VERSION 5.7 ;
  NOWIREEXTENSIONATPIN ON ;
  DIVIDERCHAR "/" ;
  BUSBITCHARS "[]" ;
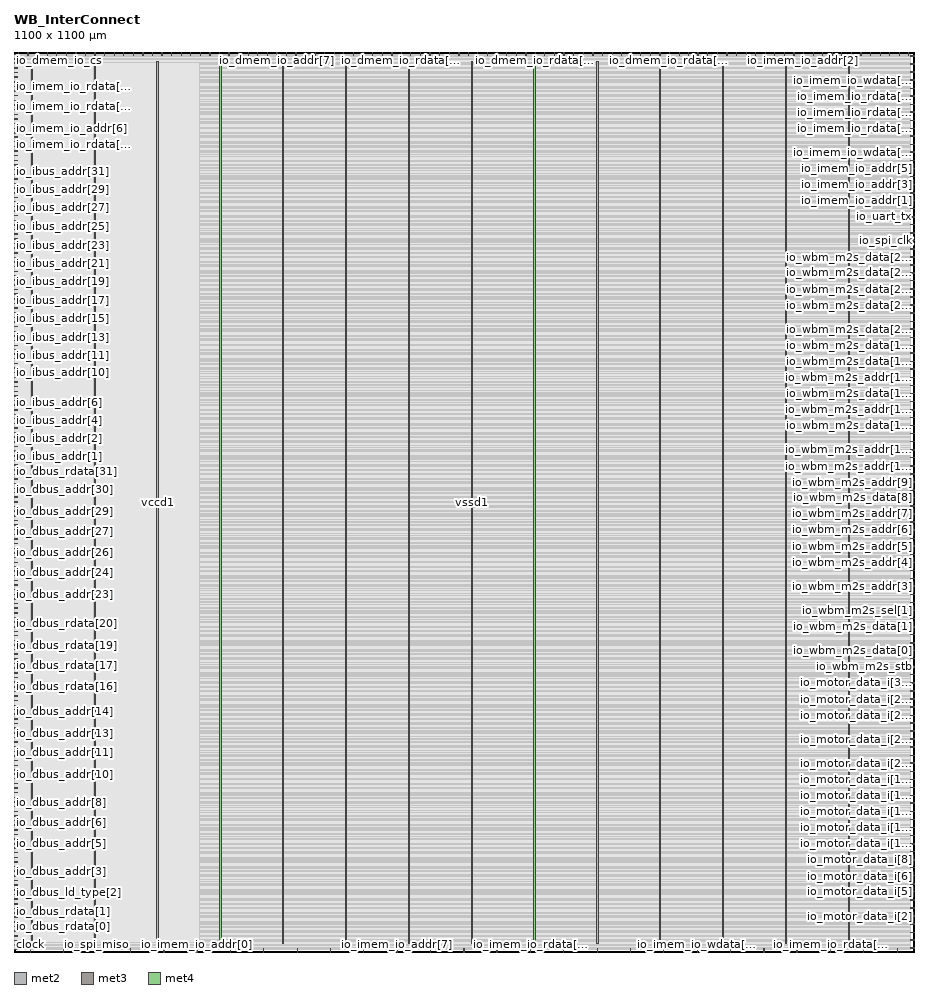
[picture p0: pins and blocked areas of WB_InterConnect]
MACRO WB_InterConnect
  CLASS BLOCK ;
  FOREIGN WB_InterConnect ;
  ORIGIN 0.000 0.000 ;
  SIZE 1100.000 BY 1100.000 ;
  PIN clock
    DIRECTION INPUT ;
    USE SIGNAL ;
    PORT
      LAYER met2 ;
        RECT 20.330 0.000 20.610 4.000 ;
    END
  END clock
  PIN io_dbus_addr[0]
    DIRECTION INPUT ;
    USE SIGNAL ;
    PORT
      LAYER met3 ;
        RECT 0.000 19.080 4.000 19.680 ;
    END
  END io_dbus_addr[0]
  PIN io_dbus_addr[10]
    DIRECTION INPUT ;
    USE SIGNAL ;
    PORT
      LAYER met3 ;
        RECT 0.000 216.960 4.000 217.560 ;
    END
  END io_dbus_addr[10]
  PIN io_dbus_addr[11]
    DIRECTION INPUT ;
    USE SIGNAL ;
    PORT
      LAYER met3 ;
        RECT 0.000 233.960 4.000 234.560 ;
    END
  END io_dbus_addr[11]
  PIN io_dbus_addr[12]
    DIRECTION INPUT ;
    USE SIGNAL ;
    PORT
      LAYER met3 ;
        RECT 0.000 250.960 4.000 251.560 ;
    END
  END io_dbus_addr[12]
  PIN io_dbus_addr[13]
    DIRECTION INPUT ;
    USE SIGNAL ;
    PORT
      LAYER met3 ;
        RECT 0.000 267.280 4.000 267.880 ;
    END
  END io_dbus_addr[13]
  PIN io_dbus_addr[14]
    DIRECTION INPUT ;
    USE SIGNAL ;
    PORT
      LAYER met3 ;
        RECT 0.000 284.280 4.000 284.880 ;
    END
  END io_dbus_addr[14]
  PIN io_dbus_addr[15]
    DIRECTION INPUT ;
    USE SIGNAL ;
    PORT
      LAYER met3 ;
        RECT 0.000 301.280 4.000 301.880 ;
    END
  END io_dbus_addr[15]
  PIN io_dbus_addr[16]
    DIRECTION INPUT ;
    USE SIGNAL ;
    PORT
      LAYER met3 ;
        RECT 0.000 318.280 4.000 318.880 ;
    END
  END io_dbus_addr[16]
  PIN io_dbus_addr[17]
    DIRECTION INPUT ;
    USE SIGNAL ;
    PORT
      LAYER met3 ;
        RECT 0.000 335.280 4.000 335.880 ;
    END
  END io_dbus_addr[17]
  PIN io_dbus_addr[18]
    DIRECTION INPUT ;
    USE SIGNAL ;
    PORT
      LAYER met3 ;
        RECT 0.000 352.280 4.000 352.880 ;
    END
  END io_dbus_addr[18]
  PIN io_dbus_addr[19]
    DIRECTION INPUT ;
    USE SIGNAL ;
    PORT
      LAYER met3 ;
        RECT 0.000 369.280 4.000 369.880 ;
    END
  END io_dbus_addr[19]
  PIN io_dbus_addr[1]
    DIRECTION INPUT ;
    USE SIGNAL ;
    PORT
      LAYER met3 ;
        RECT 0.000 47.640 4.000 48.240 ;
    END
  END io_dbus_addr[1]
  PIN io_dbus_addr[20]
    DIRECTION INPUT ;
    USE SIGNAL ;
    PORT
      LAYER met3 ;
        RECT 0.000 386.280 4.000 386.880 ;
    END
  END io_dbus_addr[20]
  PIN io_dbus_addr[21]
    DIRECTION INPUT ;
    USE SIGNAL ;
    PORT
      LAYER met3 ;
        RECT 0.000 403.280 4.000 403.880 ;
    END
  END io_dbus_addr[21]
  PIN io_dbus_addr[22]
    DIRECTION INPUT ;
    USE SIGNAL ;
    PORT
      LAYER met3 ;
        RECT 0.000 420.280 4.000 420.880 ;
    END
  END io_dbus_addr[22]
  PIN io_dbus_addr[23]
    DIRECTION INPUT ;
    USE SIGNAL ;
    PORT
      LAYER met3 ;
        RECT 0.000 436.600 4.000 437.200 ;
    END
  END io_dbus_addr[23]
  PIN io_dbus_addr[24]
    DIRECTION INPUT ;
    USE SIGNAL ;
    PORT
      LAYER met3 ;
        RECT 0.000 453.600 4.000 454.200 ;
    END
  END io_dbus_addr[24]
  PIN io_dbus_addr[25]
    DIRECTION INPUT ;
    USE SIGNAL ;
    PORT
      LAYER met3 ;
        RECT 0.000 470.600 4.000 471.200 ;
    END
  END io_dbus_addr[25]
  PIN io_dbus_addr[26]
    DIRECTION INPUT ;
    USE SIGNAL ;
    PORT
      LAYER met3 ;
        RECT 0.000 487.600 4.000 488.200 ;
    END
  END io_dbus_addr[26]
  PIN io_dbus_addr[27]
    DIRECTION INPUT ;
    USE SIGNAL ;
    PORT
      LAYER met3 ;
        RECT 0.000 504.600 4.000 505.200 ;
    END
  END io_dbus_addr[27]
  PIN io_dbus_addr[28]
    DIRECTION INPUT ;
    USE SIGNAL ;
    PORT
      LAYER met3 ;
        RECT 0.000 521.600 4.000 522.200 ;
    END
  END io_dbus_addr[28]
  PIN io_dbus_addr[29]
    DIRECTION INPUT ;
    USE SIGNAL ;
    PORT
      LAYER met3 ;
        RECT 0.000 538.600 4.000 539.200 ;
    END
  END io_dbus_addr[29]
  PIN io_dbus_addr[2]
    DIRECTION INPUT ;
    USE SIGNAL ;
    PORT
      LAYER met3 ;
        RECT 0.000 75.520 4.000 76.120 ;
    END
  END io_dbus_addr[2]
  PIN io_dbus_addr[30]
    DIRECTION INPUT ;
    USE SIGNAL ;
    PORT
      LAYER met3 ;
        RECT 0.000 555.600 4.000 556.200 ;
    END
  END io_dbus_addr[30]
  PIN io_dbus_addr[31]
    DIRECTION INPUT ;
    USE SIGNAL ;
    PORT
      LAYER met3 ;
        RECT 0.000 572.600 4.000 573.200 ;
    END
  END io_dbus_addr[31]
  PIN io_dbus_addr[3]
    DIRECTION INPUT ;
    USE SIGNAL ;
    PORT
      LAYER met3 ;
        RECT 0.000 98.640 4.000 99.240 ;
    END
  END io_dbus_addr[3]
  PIN io_dbus_addr[4]
    DIRECTION INPUT ;
    USE SIGNAL ;
    PORT
      LAYER met3 ;
        RECT 0.000 114.960 4.000 115.560 ;
    END
  END io_dbus_addr[4]
  PIN io_dbus_addr[5]
    DIRECTION INPUT ;
    USE SIGNAL ;
    PORT
      LAYER met3 ;
        RECT 0.000 131.960 4.000 132.560 ;
    END
  END io_dbus_addr[5]
  PIN io_dbus_addr[6]
    DIRECTION INPUT ;
    USE SIGNAL ;
    PORT
      LAYER met3 ;
        RECT 0.000 148.960 4.000 149.560 ;
    END
  END io_dbus_addr[6]
  PIN io_dbus_addr[7]
    DIRECTION INPUT ;
    USE SIGNAL ;
    PORT
      LAYER met3 ;
        RECT 0.000 165.960 4.000 166.560 ;
    END
  END io_dbus_addr[7]
  PIN io_dbus_addr[8]
    DIRECTION INPUT ;
    USE SIGNAL ;
    PORT
      LAYER met3 ;
        RECT 0.000 182.960 4.000 183.560 ;
    END
  END io_dbus_addr[8]
  PIN io_dbus_addr[9]
    DIRECTION INPUT ;
    USE SIGNAL ;
    PORT
      LAYER met3 ;
        RECT 0.000 199.960 4.000 200.560 ;
    END
  END io_dbus_addr[9]
  PIN io_dbus_ld_type[0]
    DIRECTION INPUT ;
    USE SIGNAL ;
    PORT
      LAYER met3 ;
        RECT 0.000 25.200 4.000 25.800 ;
    END
  END io_dbus_ld_type[0]
  PIN io_dbus_ld_type[1]
    DIRECTION INPUT ;
    USE SIGNAL ;
    PORT
      LAYER met3 ;
        RECT 0.000 53.080 4.000 53.680 ;
    END
  END io_dbus_ld_type[1]
  PIN io_dbus_ld_type[2]
    DIRECTION INPUT ;
    USE SIGNAL ;
    PORT
      LAYER met3 ;
        RECT 0.000 81.640 4.000 82.240 ;
    END
  END io_dbus_ld_type[2]
  PIN io_dbus_rd_en
    DIRECTION INPUT ;
    USE SIGNAL ;
    PORT
      LAYER met3 ;
        RECT 0.000 2.760 4.000 3.360 ;
    END
  END io_dbus_rd_en
  PIN io_dbus_rdata[0]
    DIRECTION OUTPUT TRISTATE ;
    USE SIGNAL ;
    PORT
      LAYER met3 ;
        RECT 0.000 30.640 4.000 31.240 ;
    END
  END io_dbus_rdata[0]
  PIN io_dbus_rdata[10]
    DIRECTION OUTPUT TRISTATE ;
    USE SIGNAL ;
    PORT
      LAYER met3 ;
        RECT 0.000 222.400 4.000 223.000 ;
    END
  END io_dbus_rdata[10]
  PIN io_dbus_rdata[11]
    DIRECTION OUTPUT TRISTATE ;
    USE SIGNAL ;
    PORT
      LAYER met3 ;
        RECT 0.000 239.400 4.000 240.000 ;
    END
  END io_dbus_rdata[11]
  PIN io_dbus_rdata[12]
    DIRECTION OUTPUT TRISTATE ;
    USE SIGNAL ;
    PORT
      LAYER met3 ;
        RECT 0.000 256.400 4.000 257.000 ;
    END
  END io_dbus_rdata[12]
  PIN io_dbus_rdata[13]
    DIRECTION OUTPUT TRISTATE ;
    USE SIGNAL ;
    PORT
      LAYER met3 ;
        RECT 0.000 273.400 4.000 274.000 ;
    END
  END io_dbus_rdata[13]
  PIN io_dbus_rdata[14]
    DIRECTION OUTPUT TRISTATE ;
    USE SIGNAL ;
    PORT
      LAYER met3 ;
        RECT 0.000 290.400 4.000 291.000 ;
    END
  END io_dbus_rdata[14]
  PIN io_dbus_rdata[15]
    DIRECTION OUTPUT TRISTATE ;
    USE SIGNAL ;
    PORT
      LAYER met3 ;
        RECT 0.000 307.400 4.000 308.000 ;
    END
  END io_dbus_rdata[15]
  PIN io_dbus_rdata[16]
    DIRECTION OUTPUT TRISTATE ;
    USE SIGNAL ;
    PORT
      LAYER met3 ;
        RECT 0.000 323.720 4.000 324.320 ;
    END
  END io_dbus_rdata[16]
  PIN io_dbus_rdata[17]
    DIRECTION OUTPUT TRISTATE ;
    USE SIGNAL ;
    PORT
      LAYER met3 ;
        RECT 0.000 340.720 4.000 341.320 ;
    END
  END io_dbus_rdata[17]
  PIN io_dbus_rdata[18]
    DIRECTION OUTPUT TRISTATE ;
    USE SIGNAL ;
    PORT
      LAYER met3 ;
        RECT 0.000 357.720 4.000 358.320 ;
    END
  END io_dbus_rdata[18]
  PIN io_dbus_rdata[19]
    DIRECTION OUTPUT TRISTATE ;
    USE SIGNAL ;
    PORT
      LAYER met3 ;
        RECT 0.000 374.720 4.000 375.320 ;
    END
  END io_dbus_rdata[19]
  PIN io_dbus_rdata[1]
    DIRECTION OUTPUT TRISTATE ;
    USE SIGNAL ;
    PORT
      LAYER met3 ;
        RECT 0.000 58.520 4.000 59.120 ;
    END
  END io_dbus_rdata[1]
  PIN io_dbus_rdata[20]
    DIRECTION OUTPUT TRISTATE ;
    USE SIGNAL ;
    PORT
      LAYER met3 ;
        RECT 0.000 391.720 4.000 392.320 ;
    END
  END io_dbus_rdata[20]
  PIN io_dbus_rdata[21]
    DIRECTION OUTPUT TRISTATE ;
    USE SIGNAL ;
    PORT
      LAYER met3 ;
        RECT 0.000 408.720 4.000 409.320 ;
    END
  END io_dbus_rdata[21]
  PIN io_dbus_rdata[22]
    DIRECTION OUTPUT TRISTATE ;
    USE SIGNAL ;
    PORT
      LAYER met3 ;
        RECT 0.000 425.720 4.000 426.320 ;
    END
  END io_dbus_rdata[22]
  PIN io_dbus_rdata[23]
    DIRECTION OUTPUT TRISTATE ;
    USE SIGNAL ;
    PORT
      LAYER met3 ;
        RECT 0.000 442.720 4.000 443.320 ;
    END
  END io_dbus_rdata[23]
  PIN io_dbus_rdata[24]
    DIRECTION OUTPUT TRISTATE ;
    USE SIGNAL ;
    PORT
      LAYER met3 ;
        RECT 0.000 459.720 4.000 460.320 ;
    END
  END io_dbus_rdata[24]
  PIN io_dbus_rdata[25]
    DIRECTION OUTPUT TRISTATE ;
    USE SIGNAL ;
    PORT
      LAYER met3 ;
        RECT 0.000 476.040 4.000 476.640 ;
    END
  END io_dbus_rdata[25]
  PIN io_dbus_rdata[26]
    DIRECTION OUTPUT TRISTATE ;
    USE SIGNAL ;
    PORT
      LAYER met3 ;
        RECT 0.000 493.040 4.000 493.640 ;
    END
  END io_dbus_rdata[26]
  PIN io_dbus_rdata[27]
    DIRECTION OUTPUT TRISTATE ;
    USE SIGNAL ;
    PORT
      LAYER met3 ;
        RECT 0.000 510.040 4.000 510.640 ;
    END
  END io_dbus_rdata[27]
  PIN io_dbus_rdata[28]
    DIRECTION OUTPUT TRISTATE ;
    USE SIGNAL ;
    PORT
      LAYER met3 ;
        RECT 0.000 527.040 4.000 527.640 ;
    END
  END io_dbus_rdata[28]
  PIN io_dbus_rdata[29]
    DIRECTION OUTPUT TRISTATE ;
    USE SIGNAL ;
    PORT
      LAYER met3 ;
        RECT 0.000 544.040 4.000 544.640 ;
    END
  END io_dbus_rdata[29]
  PIN io_dbus_rdata[2]
    DIRECTION OUTPUT TRISTATE ;
    USE SIGNAL ;
    PORT
      LAYER met3 ;
        RECT 0.000 87.080 4.000 87.680 ;
    END
  END io_dbus_rdata[2]
  PIN io_dbus_rdata[30]
    DIRECTION OUTPUT TRISTATE ;
    USE SIGNAL ;
    PORT
      LAYER met3 ;
        RECT 0.000 561.040 4.000 561.640 ;
    END
  END io_dbus_rdata[30]
  PIN io_dbus_rdata[31]
    DIRECTION OUTPUT TRISTATE ;
    USE SIGNAL ;
    PORT
      LAYER met3 ;
        RECT 0.000 578.040 4.000 578.640 ;
    END
  END io_dbus_rdata[31]
  PIN io_dbus_rdata[3]
    DIRECTION OUTPUT TRISTATE ;
    USE SIGNAL ;
    PORT
      LAYER met3 ;
        RECT 0.000 104.080 4.000 104.680 ;
    END
  END io_dbus_rdata[3]
  PIN io_dbus_rdata[4]
    DIRECTION OUTPUT TRISTATE ;
    USE SIGNAL ;
    PORT
      LAYER met3 ;
        RECT 0.000 121.080 4.000 121.680 ;
    END
  END io_dbus_rdata[4]
  PIN io_dbus_rdata[5]
    DIRECTION OUTPUT TRISTATE ;
    USE SIGNAL ;
    PORT
      LAYER met3 ;
        RECT 0.000 138.080 4.000 138.680 ;
    END
  END io_dbus_rdata[5]
  PIN io_dbus_rdata[6]
    DIRECTION OUTPUT TRISTATE ;
    USE SIGNAL ;
    PORT
      LAYER met3 ;
        RECT 0.000 155.080 4.000 155.680 ;
    END
  END io_dbus_rdata[6]
  PIN io_dbus_rdata[7]
    DIRECTION OUTPUT TRISTATE ;
    USE SIGNAL ;
    PORT
      LAYER met3 ;
        RECT 0.000 171.400 4.000 172.000 ;
    END
  END io_dbus_rdata[7]
  PIN io_dbus_rdata[8]
    DIRECTION OUTPUT TRISTATE ;
    USE SIGNAL ;
    PORT
      LAYER met3 ;
        RECT 0.000 188.400 4.000 189.000 ;
    END
  END io_dbus_rdata[8]
  PIN io_dbus_rdata[9]
    DIRECTION OUTPUT TRISTATE ;
    USE SIGNAL ;
    PORT
      LAYER met3 ;
        RECT 0.000 205.400 4.000 206.000 ;
    END
  END io_dbus_rdata[9]
  PIN io_dbus_st_type[0]
    DIRECTION INPUT ;
    USE SIGNAL ;
    PORT
      LAYER met3 ;
        RECT 0.000 36.080 4.000 36.680 ;
    END
  END io_dbus_st_type[0]
  PIN io_dbus_st_type[1]
    DIRECTION INPUT ;
    USE SIGNAL ;
    PORT
      LAYER met3 ;
        RECT 0.000 64.640 4.000 65.240 ;
    END
  END io_dbus_st_type[1]
  PIN io_dbus_valid
    DIRECTION OUTPUT TRISTATE ;
    USE SIGNAL ;
    PORT
      LAYER met3 ;
        RECT 0.000 8.200 4.000 8.800 ;
    END
  END io_dbus_valid
  PIN io_dbus_wdata[0]
    DIRECTION INPUT ;
    USE SIGNAL ;
    PORT
      LAYER met3 ;
        RECT 0.000 42.200 4.000 42.800 ;
    END
  END io_dbus_wdata[0]
  PIN io_dbus_wdata[10]
    DIRECTION INPUT ;
    USE SIGNAL ;
    PORT
      LAYER met3 ;
        RECT 0.000 227.840 4.000 228.440 ;
    END
  END io_dbus_wdata[10]
  PIN io_dbus_wdata[11]
    DIRECTION INPUT ;
    USE SIGNAL ;
    PORT
      LAYER met3 ;
        RECT 0.000 244.840 4.000 245.440 ;
    END
  END io_dbus_wdata[11]
  PIN io_dbus_wdata[12]
    DIRECTION INPUT ;
    USE SIGNAL ;
    PORT
      LAYER met3 ;
        RECT 0.000 261.840 4.000 262.440 ;
    END
  END io_dbus_wdata[12]
  PIN io_dbus_wdata[13]
    DIRECTION INPUT ;
    USE SIGNAL ;
    PORT
      LAYER met3 ;
        RECT 0.000 278.840 4.000 279.440 ;
    END
  END io_dbus_wdata[13]
  PIN io_dbus_wdata[14]
    DIRECTION INPUT ;
    USE SIGNAL ;
    PORT
      LAYER met3 ;
        RECT 0.000 295.840 4.000 296.440 ;
    END
  END io_dbus_wdata[14]
  PIN io_dbus_wdata[15]
    DIRECTION INPUT ;
    USE SIGNAL ;
    PORT
      LAYER met3 ;
        RECT 0.000 312.840 4.000 313.440 ;
    END
  END io_dbus_wdata[15]
  PIN io_dbus_wdata[16]
    DIRECTION INPUT ;
    USE SIGNAL ;
    PORT
      LAYER met3 ;
        RECT 0.000 329.840 4.000 330.440 ;
    END
  END io_dbus_wdata[16]
  PIN io_dbus_wdata[17]
    DIRECTION INPUT ;
    USE SIGNAL ;
    PORT
      LAYER met3 ;
        RECT 0.000 346.840 4.000 347.440 ;
    END
  END io_dbus_wdata[17]
  PIN io_dbus_wdata[18]
    DIRECTION INPUT ;
    USE SIGNAL ;
    PORT
      LAYER met3 ;
        RECT 0.000 363.840 4.000 364.440 ;
    END
  END io_dbus_wdata[18]
  PIN io_dbus_wdata[19]
    DIRECTION INPUT ;
    USE SIGNAL ;
    PORT
      LAYER met3 ;
        RECT 0.000 380.160 4.000 380.760 ;
    END
  END io_dbus_wdata[19]
  PIN io_dbus_wdata[1]
    DIRECTION INPUT ;
    USE SIGNAL ;
    PORT
      LAYER met3 ;
        RECT 0.000 70.080 4.000 70.680 ;
    END
  END io_dbus_wdata[1]
  PIN io_dbus_wdata[20]
    DIRECTION INPUT ;
    USE SIGNAL ;
    PORT
      LAYER met3 ;
        RECT 0.000 397.160 4.000 397.760 ;
    END
  END io_dbus_wdata[20]
  PIN io_dbus_wdata[21]
    DIRECTION INPUT ;
    USE SIGNAL ;
    PORT
      LAYER met3 ;
        RECT 0.000 414.160 4.000 414.760 ;
    END
  END io_dbus_wdata[21]
  PIN io_dbus_wdata[22]
    DIRECTION INPUT ;
    USE SIGNAL ;
    PORT
      LAYER met3 ;
        RECT 0.000 431.160 4.000 431.760 ;
    END
  END io_dbus_wdata[22]
  PIN io_dbus_wdata[23]
    DIRECTION INPUT ;
    USE SIGNAL ;
    PORT
      LAYER met3 ;
        RECT 0.000 448.160 4.000 448.760 ;
    END
  END io_dbus_wdata[23]
  PIN io_dbus_wdata[24]
    DIRECTION INPUT ;
    USE SIGNAL ;
    PORT
      LAYER met3 ;
        RECT 0.000 465.160 4.000 465.760 ;
    END
  END io_dbus_wdata[24]
  PIN io_dbus_wdata[25]
    DIRECTION INPUT ;
    USE SIGNAL ;
    PORT
      LAYER met3 ;
        RECT 0.000 482.160 4.000 482.760 ;
    END
  END io_dbus_wdata[25]
  PIN io_dbus_wdata[26]
    DIRECTION INPUT ;
    USE SIGNAL ;
    PORT
      LAYER met3 ;
        RECT 0.000 499.160 4.000 499.760 ;
    END
  END io_dbus_wdata[26]
  PIN io_dbus_wdata[27]
    DIRECTION INPUT ;
    USE SIGNAL ;
    PORT
      LAYER met3 ;
        RECT 0.000 516.160 4.000 516.760 ;
    END
  END io_dbus_wdata[27]
  PIN io_dbus_wdata[28]
    DIRECTION INPUT ;
    USE SIGNAL ;
    PORT
      LAYER met3 ;
        RECT 0.000 532.480 4.000 533.080 ;
    END
  END io_dbus_wdata[28]
  PIN io_dbus_wdata[29]
    DIRECTION INPUT ;
    USE SIGNAL ;
    PORT
      LAYER met3 ;
        RECT 0.000 549.480 4.000 550.080 ;
    END
  END io_dbus_wdata[29]
  PIN io_dbus_wdata[2]
    DIRECTION INPUT ;
    USE SIGNAL ;
    PORT
      LAYER met3 ;
        RECT 0.000 92.520 4.000 93.120 ;
    END
  END io_dbus_wdata[2]
  PIN io_dbus_wdata[30]
    DIRECTION INPUT ;
    USE SIGNAL ;
    PORT
      LAYER met3 ;
        RECT 0.000 566.480 4.000 567.080 ;
    END
  END io_dbus_wdata[30]
  PIN io_dbus_wdata[31]
    DIRECTION INPUT ;
    USE SIGNAL ;
    PORT
      LAYER met3 ;
        RECT 0.000 583.480 4.000 584.080 ;
    END
  END io_dbus_wdata[31]
  PIN io_dbus_wdata[3]
    DIRECTION INPUT ;
    USE SIGNAL ;
    PORT
      LAYER met3 ;
        RECT 0.000 109.520 4.000 110.120 ;
    END
  END io_dbus_wdata[3]
  PIN io_dbus_wdata[4]
    DIRECTION INPUT ;
    USE SIGNAL ;
    PORT
      LAYER met3 ;
        RECT 0.000 126.520 4.000 127.120 ;
    END
  END io_dbus_wdata[4]
  PIN io_dbus_wdata[5]
    DIRECTION INPUT ;
    USE SIGNAL ;
    PORT
      LAYER met3 ;
        RECT 0.000 143.520 4.000 144.120 ;
    END
  END io_dbus_wdata[5]
  PIN io_dbus_wdata[6]
    DIRECTION INPUT ;
    USE SIGNAL ;
    PORT
      LAYER met3 ;
        RECT 0.000 160.520 4.000 161.120 ;
    END
  END io_dbus_wdata[6]
  PIN io_dbus_wdata[7]
    DIRECTION INPUT ;
    USE SIGNAL ;
    PORT
      LAYER met3 ;
        RECT 0.000 177.520 4.000 178.120 ;
    END
  END io_dbus_wdata[7]
  PIN io_dbus_wdata[8]
    DIRECTION INPUT ;
    USE SIGNAL ;
    PORT
      LAYER met3 ;
        RECT 0.000 194.520 4.000 195.120 ;
    END
  END io_dbus_wdata[8]
  PIN io_dbus_wdata[9]
    DIRECTION INPUT ;
    USE SIGNAL ;
    PORT
      LAYER met3 ;
        RECT 0.000 211.520 4.000 212.120 ;
    END
  END io_dbus_wdata[9]
  PIN io_dbus_wr_en
    DIRECTION INPUT ;
    USE SIGNAL ;
    PORT
      LAYER met3 ;
        RECT 0.000 13.640 4.000 14.240 ;
    END
  END io_dbus_wr_en
  PIN io_dmem_io_addr[0]
    DIRECTION OUTPUT TRISTATE ;
    USE SIGNAL ;
    PORT
      LAYER met2 ;
        RECT 28.610 1096.000 28.890 1100.000 ;
    END
  END io_dmem_io_addr[0]
  PIN io_dmem_io_addr[1]
    DIRECTION OUTPUT TRISTATE ;
    USE SIGNAL ;
    PORT
      LAYER met2 ;
        RECT 75.530 1096.000 75.810 1100.000 ;
    END
  END io_dmem_io_addr[1]
  PIN io_dmem_io_addr[2]
    DIRECTION OUTPUT TRISTATE ;
    USE SIGNAL ;
    PORT
      LAYER met2 ;
        RECT 122.450 1096.000 122.730 1100.000 ;
    END
  END io_dmem_io_addr[2]
  PIN io_dmem_io_addr[3]
    DIRECTION OUTPUT TRISTATE ;
    USE SIGNAL ;
    PORT
      LAYER met2 ;
        RECT 169.370 1096.000 169.650 1100.000 ;
    END
  END io_dmem_io_addr[3]
  PIN io_dmem_io_addr[4]
    DIRECTION OUTPUT TRISTATE ;
    USE SIGNAL ;
    PORT
      LAYER met2 ;
        RECT 215.830 1096.000 216.110 1100.000 ;
    END
  END io_dmem_io_addr[4]
  PIN io_dmem_io_addr[5]
    DIRECTION OUTPUT TRISTATE ;
    USE SIGNAL ;
    PORT
      LAYER met2 ;
        RECT 251.250 1096.000 251.530 1100.000 ;
    END
  END io_dmem_io_addr[5]
  PIN io_dmem_io_addr[6]
    DIRECTION OUTPUT TRISTATE ;
    USE SIGNAL ;
    PORT
      LAYER met2 ;
        RECT 286.210 1096.000 286.490 1100.000 ;
    END
  END io_dmem_io_addr[6]
  PIN io_dmem_io_addr[7]
    DIRECTION OUTPUT TRISTATE ;
    USE SIGNAL ;
    PORT
      LAYER met2 ;
        RECT 321.170 1096.000 321.450 1100.000 ;
    END
  END io_dmem_io_addr[7]
  PIN io_dmem_io_cs
    DIRECTION OUTPUT TRISTATE ;
    USE SIGNAL ;
    PORT
      LAYER met2 ;
        RECT 5.610 1096.000 5.890 1100.000 ;
    END
  END io_dmem_io_cs
  PIN io_dmem_io_rdata[0]
    DIRECTION INPUT ;
    USE SIGNAL ;
    PORT
      LAYER met2 ;
        RECT 40.570 1096.000 40.850 1100.000 ;
    END
  END io_dmem_io_rdata[0]
  PIN io_dmem_io_rdata[10]
    DIRECTION INPUT ;
    USE SIGNAL ;
    PORT
      LAYER met2 ;
        RECT 403.050 1096.000 403.330 1100.000 ;
    END
  END io_dmem_io_rdata[10]
  PIN io_dmem_io_rdata[11]
    DIRECTION INPUT ;
    USE SIGNAL ;
    PORT
      LAYER met2 ;
        RECT 426.510 1096.000 426.790 1100.000 ;
    END
  END io_dmem_io_rdata[11]
  PIN io_dmem_io_rdata[12]
    DIRECTION INPUT ;
    USE SIGNAL ;
    PORT
      LAYER met2 ;
        RECT 449.970 1096.000 450.250 1100.000 ;
    END
  END io_dmem_io_rdata[12]
  PIN io_dmem_io_rdata[13]
    DIRECTION INPUT ;
    USE SIGNAL ;
    PORT
      LAYER met2 ;
        RECT 473.430 1096.000 473.710 1100.000 ;
    END
  END io_dmem_io_rdata[13]
  PIN io_dmem_io_rdata[14]
    DIRECTION INPUT ;
    USE SIGNAL ;
    PORT
      LAYER met2 ;
        RECT 496.890 1096.000 497.170 1100.000 ;
    END
  END io_dmem_io_rdata[14]
  PIN io_dmem_io_rdata[15]
    DIRECTION INPUT ;
    USE SIGNAL ;
    PORT
      LAYER met2 ;
        RECT 520.350 1096.000 520.630 1100.000 ;
    END
  END io_dmem_io_rdata[15]
  PIN io_dmem_io_rdata[16]
    DIRECTION INPUT ;
    USE SIGNAL ;
    PORT
      LAYER met2 ;
        RECT 543.810 1096.000 544.090 1100.000 ;
    END
  END io_dmem_io_rdata[16]
  PIN io_dmem_io_rdata[17]
    DIRECTION INPUT ;
    USE SIGNAL ;
    PORT
      LAYER met2 ;
        RECT 566.810 1096.000 567.090 1100.000 ;
    END
  END io_dmem_io_rdata[17]
  PIN io_dmem_io_rdata[18]
    DIRECTION INPUT ;
    USE SIGNAL ;
    PORT
      LAYER met2 ;
        RECT 590.270 1096.000 590.550 1100.000 ;
    END
  END io_dmem_io_rdata[18]
  PIN io_dmem_io_rdata[19]
    DIRECTION INPUT ;
    USE SIGNAL ;
    PORT
      LAYER met2 ;
        RECT 613.730 1096.000 614.010 1100.000 ;
    END
  END io_dmem_io_rdata[19]
  PIN io_dmem_io_rdata[1]
    DIRECTION INPUT ;
    USE SIGNAL ;
    PORT
      LAYER met2 ;
        RECT 87.490 1096.000 87.770 1100.000 ;
    END
  END io_dmem_io_rdata[1]
  PIN io_dmem_io_rdata[20]
    DIRECTION INPUT ;
    USE SIGNAL ;
    PORT
      LAYER met2 ;
        RECT 637.190 1096.000 637.470 1100.000 ;
    END
  END io_dmem_io_rdata[20]
  PIN io_dmem_io_rdata[21]
    DIRECTION INPUT ;
    USE SIGNAL ;
    PORT
      LAYER met2 ;
        RECT 660.650 1096.000 660.930 1100.000 ;
    END
  END io_dmem_io_rdata[21]
  PIN io_dmem_io_rdata[22]
    DIRECTION INPUT ;
    USE SIGNAL ;
    PORT
      LAYER met2 ;
        RECT 684.110 1096.000 684.390 1100.000 ;
    END
  END io_dmem_io_rdata[22]
  PIN io_dmem_io_rdata[23]
    DIRECTION INPUT ;
    USE SIGNAL ;
    PORT
      LAYER met2 ;
        RECT 707.570 1096.000 707.850 1100.000 ;
    END
  END io_dmem_io_rdata[23]
  PIN io_dmem_io_rdata[24]
    DIRECTION INPUT ;
    USE SIGNAL ;
    PORT
      LAYER met2 ;
        RECT 731.030 1096.000 731.310 1100.000 ;
    END
  END io_dmem_io_rdata[24]
  PIN io_dmem_io_rdata[25]
    DIRECTION INPUT ;
    USE SIGNAL ;
    PORT
      LAYER met2 ;
        RECT 754.030 1096.000 754.310 1100.000 ;
    END
  END io_dmem_io_rdata[25]
  PIN io_dmem_io_rdata[26]
    DIRECTION INPUT ;
    USE SIGNAL ;
    PORT
      LAYER met2 ;
        RECT 777.490 1096.000 777.770 1100.000 ;
    END
  END io_dmem_io_rdata[26]
  PIN io_dmem_io_rdata[27]
    DIRECTION INPUT ;
    USE SIGNAL ;
    PORT
      LAYER met2 ;
        RECT 800.950 1096.000 801.230 1100.000 ;
    END
  END io_dmem_io_rdata[27]
  PIN io_dmem_io_rdata[28]
    DIRECTION INPUT ;
    USE SIGNAL ;
    PORT
      LAYER met2 ;
        RECT 824.410 1096.000 824.690 1100.000 ;
    END
  END io_dmem_io_rdata[28]
  PIN io_dmem_io_rdata[29]
    DIRECTION INPUT ;
    USE SIGNAL ;
    PORT
      LAYER met2 ;
        RECT 847.870 1096.000 848.150 1100.000 ;
    END
  END io_dmem_io_rdata[29]
  PIN io_dmem_io_rdata[2]
    DIRECTION INPUT ;
    USE SIGNAL ;
    PORT
      LAYER met2 ;
        RECT 133.950 1096.000 134.230 1100.000 ;
    END
  END io_dmem_io_rdata[2]
  PIN io_dmem_io_rdata[30]
    DIRECTION INPUT ;
    USE SIGNAL ;
    PORT
      LAYER met2 ;
        RECT 871.330 1096.000 871.610 1100.000 ;
    END
  END io_dmem_io_rdata[30]
  PIN io_dmem_io_rdata[31]
    DIRECTION INPUT ;
    USE SIGNAL ;
    PORT
      LAYER met2 ;
        RECT 894.790 1096.000 895.070 1100.000 ;
    END
  END io_dmem_io_rdata[31]
  PIN io_dmem_io_rdata[3]
    DIRECTION INPUT ;
    USE SIGNAL ;
    PORT
      LAYER met2 ;
        RECT 180.870 1096.000 181.150 1100.000 ;
    END
  END io_dmem_io_rdata[3]
  PIN io_dmem_io_rdata[4]
    DIRECTION INPUT ;
    USE SIGNAL ;
    PORT
      LAYER met2 ;
        RECT 227.790 1096.000 228.070 1100.000 ;
    END
  END io_dmem_io_rdata[4]
  PIN io_dmem_io_rdata[5]
    DIRECTION INPUT ;
    USE SIGNAL ;
    PORT
      LAYER met2 ;
        RECT 262.750 1096.000 263.030 1100.000 ;
    END
  END io_dmem_io_rdata[5]
  PIN io_dmem_io_rdata[6]
    DIRECTION INPUT ;
    USE SIGNAL ;
    PORT
      LAYER met2 ;
        RECT 297.710 1096.000 297.990 1100.000 ;
    END
  END io_dmem_io_rdata[6]
  PIN io_dmem_io_rdata[7]
    DIRECTION INPUT ;
    USE SIGNAL ;
    PORT
      LAYER met2 ;
        RECT 333.130 1096.000 333.410 1100.000 ;
    END
  END io_dmem_io_rdata[7]
  PIN io_dmem_io_rdata[8]
    DIRECTION INPUT ;
    USE SIGNAL ;
    PORT
      LAYER met2 ;
        RECT 356.590 1096.000 356.870 1100.000 ;
    END
  END io_dmem_io_rdata[8]
  PIN io_dmem_io_rdata[9]
    DIRECTION INPUT ;
    USE SIGNAL ;
    PORT
      LAYER met2 ;
        RECT 379.590 1096.000 379.870 1100.000 ;
    END
  END io_dmem_io_rdata[9]
  PIN io_dmem_io_st_type[0]
    DIRECTION OUTPUT TRISTATE ;
    USE SIGNAL ;
    PORT
      LAYER met2 ;
        RECT 52.070 1096.000 52.350 1100.000 ;
    END
  END io_dmem_io_st_type[0]
  PIN io_dmem_io_st_type[1]
    DIRECTION OUTPUT TRISTATE ;
    USE SIGNAL ;
    PORT
      LAYER met2 ;
        RECT 98.990 1096.000 99.270 1100.000 ;
    END
  END io_dmem_io_st_type[1]
  PIN io_dmem_io_st_type[2]
    DIRECTION OUTPUT TRISTATE ;
    USE SIGNAL ;
    PORT
      LAYER met2 ;
        RECT 145.910 1096.000 146.190 1100.000 ;
    END
  END io_dmem_io_st_type[2]
  PIN io_dmem_io_st_type[3]
    DIRECTION OUTPUT TRISTATE ;
    USE SIGNAL ;
    PORT
      LAYER met2 ;
        RECT 192.370 1096.000 192.650 1100.000 ;
    END
  END io_dmem_io_st_type[3]
  PIN io_dmem_io_wdata[0]
    DIRECTION OUTPUT TRISTATE ;
    USE SIGNAL ;
    PORT
      LAYER met2 ;
        RECT 64.030 1096.000 64.310 1100.000 ;
    END
  END io_dmem_io_wdata[0]
  PIN io_dmem_io_wdata[10]
    DIRECTION OUTPUT TRISTATE ;
    USE SIGNAL ;
    PORT
      LAYER met2 ;
        RECT 415.010 1096.000 415.290 1100.000 ;
    END
  END io_dmem_io_wdata[10]
  PIN io_dmem_io_wdata[11]
    DIRECTION OUTPUT TRISTATE ;
    USE SIGNAL ;
    PORT
      LAYER met2 ;
        RECT 438.470 1096.000 438.750 1100.000 ;
    END
  END io_dmem_io_wdata[11]
  PIN io_dmem_io_wdata[12]
    DIRECTION OUTPUT TRISTATE ;
    USE SIGNAL ;
    PORT
      LAYER met2 ;
        RECT 461.930 1096.000 462.210 1100.000 ;
    END
  END io_dmem_io_wdata[12]
  PIN io_dmem_io_wdata[13]
    DIRECTION OUTPUT TRISTATE ;
    USE SIGNAL ;
    PORT
      LAYER met2 ;
        RECT 484.930 1096.000 485.210 1100.000 ;
    END
  END io_dmem_io_wdata[13]
  PIN io_dmem_io_wdata[14]
    DIRECTION OUTPUT TRISTATE ;
    USE SIGNAL ;
    PORT
      LAYER met2 ;
        RECT 508.390 1096.000 508.670 1100.000 ;
    END
  END io_dmem_io_wdata[14]
  PIN io_dmem_io_wdata[15]
    DIRECTION OUTPUT TRISTATE ;
    USE SIGNAL ;
    PORT
      LAYER met2 ;
        RECT 531.850 1096.000 532.130 1100.000 ;
    END
  END io_dmem_io_wdata[15]
  PIN io_dmem_io_wdata[16]
    DIRECTION OUTPUT TRISTATE ;
    USE SIGNAL ;
    PORT
      LAYER met2 ;
        RECT 555.310 1096.000 555.590 1100.000 ;
    END
  END io_dmem_io_wdata[16]
  PIN io_dmem_io_wdata[17]
    DIRECTION OUTPUT TRISTATE ;
    USE SIGNAL ;
    PORT
      LAYER met2 ;
        RECT 578.770 1096.000 579.050 1100.000 ;
    END
  END io_dmem_io_wdata[17]
  PIN io_dmem_io_wdata[18]
    DIRECTION OUTPUT TRISTATE ;
    USE SIGNAL ;
    PORT
      LAYER met2 ;
        RECT 602.230 1096.000 602.510 1100.000 ;
    END
  END io_dmem_io_wdata[18]
  PIN io_dmem_io_wdata[19]
    DIRECTION OUTPUT TRISTATE ;
    USE SIGNAL ;
    PORT
      LAYER met2 ;
        RECT 625.690 1096.000 625.970 1100.000 ;
    END
  END io_dmem_io_wdata[19]
  PIN io_dmem_io_wdata[1]
    DIRECTION OUTPUT TRISTATE ;
    USE SIGNAL ;
    PORT
      LAYER met2 ;
        RECT 110.490 1096.000 110.770 1100.000 ;
    END
  END io_dmem_io_wdata[1]
  PIN io_dmem_io_wdata[20]
    DIRECTION OUTPUT TRISTATE ;
    USE SIGNAL ;
    PORT
      LAYER met2 ;
        RECT 648.690 1096.000 648.970 1100.000 ;
    END
  END io_dmem_io_wdata[20]
  PIN io_dmem_io_wdata[21]
    DIRECTION OUTPUT TRISTATE ;
    USE SIGNAL ;
    PORT
      LAYER met2 ;
        RECT 672.150 1096.000 672.430 1100.000 ;
    END
  END io_dmem_io_wdata[21]
  PIN io_dmem_io_wdata[22]
    DIRECTION OUTPUT TRISTATE ;
    USE SIGNAL ;
    PORT
      LAYER met2 ;
        RECT 695.610 1096.000 695.890 1100.000 ;
    END
  END io_dmem_io_wdata[22]
  PIN io_dmem_io_wdata[23]
    DIRECTION OUTPUT TRISTATE ;
    USE SIGNAL ;
    PORT
      LAYER met2 ;
        RECT 719.070 1096.000 719.350 1100.000 ;
    END
  END io_dmem_io_wdata[23]
  PIN io_dmem_io_wdata[24]
    DIRECTION OUTPUT TRISTATE ;
    USE SIGNAL ;
    PORT
      LAYER met2 ;
        RECT 742.530 1096.000 742.810 1100.000 ;
    END
  END io_dmem_io_wdata[24]
  PIN io_dmem_io_wdata[25]
    DIRECTION OUTPUT TRISTATE ;
    USE SIGNAL ;
    PORT
      LAYER met2 ;
        RECT 765.990 1096.000 766.270 1100.000 ;
    END
  END io_dmem_io_wdata[25]
  PIN io_dmem_io_wdata[26]
    DIRECTION OUTPUT TRISTATE ;
    USE SIGNAL ;
    PORT
      LAYER met2 ;
        RECT 789.450 1096.000 789.730 1100.000 ;
    END
  END io_dmem_io_wdata[26]
  PIN io_dmem_io_wdata[27]
    DIRECTION OUTPUT TRISTATE ;
    USE SIGNAL ;
    PORT
      LAYER met2 ;
        RECT 812.910 1096.000 813.190 1100.000 ;
    END
  END io_dmem_io_wdata[27]
  PIN io_dmem_io_wdata[28]
    DIRECTION OUTPUT TRISTATE ;
    USE SIGNAL ;
    PORT
      LAYER met2 ;
        RECT 835.910 1096.000 836.190 1100.000 ;
    END
  END io_dmem_io_wdata[28]
  PIN io_dmem_io_wdata[29]
    DIRECTION OUTPUT TRISTATE ;
    USE SIGNAL ;
    PORT
      LAYER met2 ;
        RECT 859.370 1096.000 859.650 1100.000 ;
    END
  END io_dmem_io_wdata[29]
  PIN io_dmem_io_wdata[2]
    DIRECTION OUTPUT TRISTATE ;
    USE SIGNAL ;
    PORT
      LAYER met2 ;
        RECT 157.410 1096.000 157.690 1100.000 ;
    END
  END io_dmem_io_wdata[2]
  PIN io_dmem_io_wdata[30]
    DIRECTION OUTPUT TRISTATE ;
    USE SIGNAL ;
    PORT
      LAYER met2 ;
        RECT 882.830 1096.000 883.110 1100.000 ;
    END
  END io_dmem_io_wdata[30]
  PIN io_dmem_io_wdata[31]
    DIRECTION OUTPUT TRISTATE ;
    USE SIGNAL ;
    PORT
      LAYER met2 ;
        RECT 906.290 1096.000 906.570 1100.000 ;
    END
  END io_dmem_io_wdata[31]
  PIN io_dmem_io_wdata[3]
    DIRECTION OUTPUT TRISTATE ;
    USE SIGNAL ;
    PORT
      LAYER met2 ;
        RECT 204.330 1096.000 204.610 1100.000 ;
    END
  END io_dmem_io_wdata[3]
  PIN io_dmem_io_wdata[4]
    DIRECTION OUTPUT TRISTATE ;
    USE SIGNAL ;
    PORT
      LAYER met2 ;
        RECT 239.290 1096.000 239.570 1100.000 ;
    END
  END io_dmem_io_wdata[4]
  PIN io_dmem_io_wdata[5]
    DIRECTION OUTPUT TRISTATE ;
    USE SIGNAL ;
    PORT
      LAYER met2 ;
        RECT 274.710 1096.000 274.990 1100.000 ;
    END
  END io_dmem_io_wdata[5]
  PIN io_dmem_io_wdata[6]
    DIRECTION OUTPUT TRISTATE ;
    USE SIGNAL ;
    PORT
      LAYER met2 ;
        RECT 309.670 1096.000 309.950 1100.000 ;
    END
  END io_dmem_io_wdata[6]
  PIN io_dmem_io_wdata[7]
    DIRECTION OUTPUT TRISTATE ;
    USE SIGNAL ;
    PORT
      LAYER met2 ;
        RECT 344.630 1096.000 344.910 1100.000 ;
    END
  END io_dmem_io_wdata[7]
  PIN io_dmem_io_wdata[8]
    DIRECTION OUTPUT TRISTATE ;
    USE SIGNAL ;
    PORT
      LAYER met2 ;
        RECT 368.090 1096.000 368.370 1100.000 ;
    END
  END io_dmem_io_wdata[8]
  PIN io_dmem_io_wdata[9]
    DIRECTION OUTPUT TRISTATE ;
    USE SIGNAL ;
    PORT
      LAYER met2 ;
        RECT 391.550 1096.000 391.830 1100.000 ;
    END
  END io_dmem_io_wdata[9]
  PIN io_dmem_io_wr_en
    DIRECTION OUTPUT TRISTATE ;
    USE SIGNAL ;
    PORT
      LAYER met2 ;
        RECT 17.110 1096.000 17.390 1100.000 ;
    END
  END io_dmem_io_wr_en
  PIN io_ibus_addr[0]
    DIRECTION INPUT ;
    USE SIGNAL ;
    PORT
      LAYER met3 ;
        RECT 0.000 595.040 4.000 595.640 ;
    END
  END io_ibus_addr[0]
  PIN io_ibus_addr[10]
    DIRECTION INPUT ;
    USE SIGNAL ;
    PORT
      LAYER met3 ;
        RECT 0.000 707.920 4.000 708.520 ;
    END
  END io_ibus_addr[10]
  PIN io_ibus_addr[11]
    DIRECTION INPUT ;
    USE SIGNAL ;
    PORT
      LAYER met3 ;
        RECT 0.000 718.800 4.000 719.400 ;
    END
  END io_ibus_addr[11]
  PIN io_ibus_addr[12]
    DIRECTION INPUT ;
    USE SIGNAL ;
    PORT
      LAYER met3 ;
        RECT 0.000 730.360 4.000 730.960 ;
    END
  END io_ibus_addr[12]
  PIN io_ibus_addr[13]
    DIRECTION INPUT ;
    USE SIGNAL ;
    PORT
      LAYER met3 ;
        RECT 0.000 741.240 4.000 741.840 ;
    END
  END io_ibus_addr[13]
  PIN io_ibus_addr[14]
    DIRECTION INPUT ;
    USE SIGNAL ;
    PORT
      LAYER met3 ;
        RECT 0.000 752.800 4.000 753.400 ;
    END
  END io_ibus_addr[14]
  PIN io_ibus_addr[15]
    DIRECTION INPUT ;
    USE SIGNAL ;
    PORT
      LAYER met3 ;
        RECT 0.000 764.360 4.000 764.960 ;
    END
  END io_ibus_addr[15]
  PIN io_ibus_addr[16]
    DIRECTION INPUT ;
    USE SIGNAL ;
    PORT
      LAYER met3 ;
        RECT 0.000 775.240 4.000 775.840 ;
    END
  END io_ibus_addr[16]
  PIN io_ibus_addr[17]
    DIRECTION INPUT ;
    USE SIGNAL ;
    PORT
      LAYER met3 ;
        RECT 0.000 786.800 4.000 787.400 ;
    END
  END io_ibus_addr[17]
  PIN io_ibus_addr[18]
    DIRECTION INPUT ;
    USE SIGNAL ;
    PORT
      LAYER met3 ;
        RECT 0.000 797.680 4.000 798.280 ;
    END
  END io_ibus_addr[18]
  PIN io_ibus_addr[19]
    DIRECTION INPUT ;
    USE SIGNAL ;
    PORT
      LAYER met3 ;
        RECT 0.000 809.240 4.000 809.840 ;
    END
  END io_ibus_addr[19]
  PIN io_ibus_addr[1]
    DIRECTION INPUT ;
    USE SIGNAL ;
    PORT
      LAYER met3 ;
        RECT 0.000 605.920 4.000 606.520 ;
    END
  END io_ibus_addr[1]
  PIN io_ibus_addr[20]
    DIRECTION INPUT ;
    USE SIGNAL ;
    PORT
      LAYER met3 ;
        RECT 0.000 820.800 4.000 821.400 ;
    END
  END io_ibus_addr[20]
  PIN io_ibus_addr[21]
    DIRECTION INPUT ;
    USE SIGNAL ;
    PORT
      LAYER met3 ;
        RECT 0.000 831.680 4.000 832.280 ;
    END
  END io_ibus_addr[21]
  PIN io_ibus_addr[22]
    DIRECTION INPUT ;
    USE SIGNAL ;
    PORT
      LAYER met3 ;
        RECT 0.000 843.240 4.000 843.840 ;
    END
  END io_ibus_addr[22]
  PIN io_ibus_addr[23]
    DIRECTION INPUT ;
    USE SIGNAL ;
    PORT
      LAYER met3 ;
        RECT 0.000 854.120 4.000 854.720 ;
    END
  END io_ibus_addr[23]
  PIN io_ibus_addr[24]
    DIRECTION INPUT ;
    USE SIGNAL ;
    PORT
      LAYER met3 ;
        RECT 0.000 865.680 4.000 866.280 ;
    END
  END io_ibus_addr[24]
  PIN io_ibus_addr[25]
    DIRECTION INPUT ;
    USE SIGNAL ;
    PORT
      LAYER met3 ;
        RECT 0.000 877.240 4.000 877.840 ;
    END
  END io_ibus_addr[25]
  PIN io_ibus_addr[26]
    DIRECTION INPUT ;
    USE SIGNAL ;
    PORT
      LAYER met3 ;
        RECT 0.000 888.120 4.000 888.720 ;
    END
  END io_ibus_addr[26]
  PIN io_ibus_addr[27]
    DIRECTION INPUT ;
    USE SIGNAL ;
    PORT
      LAYER met3 ;
        RECT 0.000 899.680 4.000 900.280 ;
    END
  END io_ibus_addr[27]
  PIN io_ibus_addr[28]
    DIRECTION INPUT ;
    USE SIGNAL ;
    PORT
      LAYER met3 ;
        RECT 0.000 910.560 4.000 911.160 ;
    END
  END io_ibus_addr[28]
  PIN io_ibus_addr[29]
    DIRECTION INPUT ;
    USE SIGNAL ;
    PORT
      LAYER met3 ;
        RECT 0.000 922.120 4.000 922.720 ;
    END
  END io_ibus_addr[29]
  PIN io_ibus_addr[2]
    DIRECTION INPUT ;
    USE SIGNAL ;
    PORT
      LAYER met3 ;
        RECT 0.000 617.480 4.000 618.080 ;
    END
  END io_ibus_addr[2]
  PIN io_ibus_addr[30]
    DIRECTION INPUT ;
    USE SIGNAL ;
    PORT
      LAYER met3 ;
        RECT 0.000 933.680 4.000 934.280 ;
    END
  END io_ibus_addr[30]
  PIN io_ibus_addr[31]
    DIRECTION INPUT ;
    USE SIGNAL ;
    PORT
      LAYER met3 ;
        RECT 0.000 944.560 4.000 945.160 ;
    END
  END io_ibus_addr[31]
  PIN io_ibus_addr[3]
    DIRECTION INPUT ;
    USE SIGNAL ;
    PORT
      LAYER met3 ;
        RECT 0.000 629.040 4.000 629.640 ;
    END
  END io_ibus_addr[3]
  PIN io_ibus_addr[4]
    DIRECTION INPUT ;
    USE SIGNAL ;
    PORT
      LAYER met3 ;
        RECT 0.000 639.920 4.000 640.520 ;
    END
  END io_ibus_addr[4]
  PIN io_ibus_addr[5]
    DIRECTION INPUT ;
    USE SIGNAL ;
    PORT
      LAYER met3 ;
        RECT 0.000 651.480 4.000 652.080 ;
    END
  END io_ibus_addr[5]
  PIN io_ibus_addr[6]
    DIRECTION INPUT ;
    USE SIGNAL ;
    PORT
      LAYER met3 ;
        RECT 0.000 662.360 4.000 662.960 ;
    END
  END io_ibus_addr[6]
  PIN io_ibus_addr[7]
    DIRECTION INPUT ;
    USE SIGNAL ;
    PORT
      LAYER met3 ;
        RECT 0.000 673.920 4.000 674.520 ;
    END
  END io_ibus_addr[7]
  PIN io_ibus_addr[8]
    DIRECTION INPUT ;
    USE SIGNAL ;
    PORT
      LAYER met3 ;
        RECT 0.000 684.800 4.000 685.400 ;
    END
  END io_ibus_addr[8]
  PIN io_ibus_addr[9]
    DIRECTION INPUT ;
    USE SIGNAL ;
    PORT
      LAYER met3 ;
        RECT 0.000 696.360 4.000 696.960 ;
    END
  END io_ibus_addr[9]
  PIN io_ibus_inst[0]
    DIRECTION OUTPUT TRISTATE ;
    USE SIGNAL ;
    PORT
      LAYER met3 ;
        RECT 0.000 600.480 4.000 601.080 ;
    END
  END io_ibus_inst[0]
  PIN io_ibus_inst[10]
    DIRECTION OUTPUT TRISTATE ;
    USE SIGNAL ;
    PORT
      LAYER met3 ;
        RECT 0.000 713.360 4.000 713.960 ;
    END
  END io_ibus_inst[10]
  PIN io_ibus_inst[11]
    DIRECTION OUTPUT TRISTATE ;
    USE SIGNAL ;
    PORT
      LAYER met3 ;
        RECT 0.000 724.920 4.000 725.520 ;
    END
  END io_ibus_inst[11]
  PIN io_ibus_inst[12]
    DIRECTION OUTPUT TRISTATE ;
    USE SIGNAL ;
    PORT
      LAYER met3 ;
        RECT 0.000 735.800 4.000 736.400 ;
    END
  END io_ibus_inst[12]
  PIN io_ibus_inst[13]
    DIRECTION OUTPUT TRISTATE ;
    USE SIGNAL ;
    PORT
      LAYER met3 ;
        RECT 0.000 747.360 4.000 747.960 ;
    END
  END io_ibus_inst[13]
  PIN io_ibus_inst[14]
    DIRECTION OUTPUT TRISTATE ;
    USE SIGNAL ;
    PORT
      LAYER met3 ;
        RECT 0.000 758.240 4.000 758.840 ;
    END
  END io_ibus_inst[14]
  PIN io_ibus_inst[15]
    DIRECTION OUTPUT TRISTATE ;
    USE SIGNAL ;
    PORT
      LAYER met3 ;
        RECT 0.000 769.800 4.000 770.400 ;
    END
  END io_ibus_inst[15]
  PIN io_ibus_inst[16]
    DIRECTION OUTPUT TRISTATE ;
    USE SIGNAL ;
    PORT
      LAYER met3 ;
        RECT 0.000 781.360 4.000 781.960 ;
    END
  END io_ibus_inst[16]
  PIN io_ibus_inst[17]
    DIRECTION OUTPUT TRISTATE ;
    USE SIGNAL ;
    PORT
      LAYER met3 ;
        RECT 0.000 792.240 4.000 792.840 ;
    END
  END io_ibus_inst[17]
  PIN io_ibus_inst[18]
    DIRECTION OUTPUT TRISTATE ;
    USE SIGNAL ;
    PORT
      LAYER met3 ;
        RECT 0.000 803.800 4.000 804.400 ;
    END
  END io_ibus_inst[18]
  PIN io_ibus_inst[19]
    DIRECTION OUTPUT TRISTATE ;
    USE SIGNAL ;
    PORT
      LAYER met3 ;
        RECT 0.000 814.680 4.000 815.280 ;
    END
  END io_ibus_inst[19]
  PIN io_ibus_inst[1]
    DIRECTION OUTPUT TRISTATE ;
    USE SIGNAL ;
    PORT
      LAYER met3 ;
        RECT 0.000 612.040 4.000 612.640 ;
    END
  END io_ibus_inst[1]
  PIN io_ibus_inst[20]
    DIRECTION OUTPUT TRISTATE ;
    USE SIGNAL ;
    PORT
      LAYER met3 ;
        RECT 0.000 826.240 4.000 826.840 ;
    END
  END io_ibus_inst[20]
  PIN io_ibus_inst[21]
    DIRECTION OUTPUT TRISTATE ;
    USE SIGNAL ;
    PORT
      LAYER met3 ;
        RECT 0.000 837.800 4.000 838.400 ;
    END
  END io_ibus_inst[21]
  PIN io_ibus_inst[22]
    DIRECTION OUTPUT TRISTATE ;
    USE SIGNAL ;
    PORT
      LAYER met3 ;
        RECT 0.000 848.680 4.000 849.280 ;
    END
  END io_ibus_inst[22]
  PIN io_ibus_inst[23]
    DIRECTION OUTPUT TRISTATE ;
    USE SIGNAL ;
    PORT
      LAYER met3 ;
        RECT 0.000 860.240 4.000 860.840 ;
    END
  END io_ibus_inst[23]
  PIN io_ibus_inst[24]
    DIRECTION OUTPUT TRISTATE ;
    USE SIGNAL ;
    PORT
      LAYER met3 ;
        RECT 0.000 871.120 4.000 871.720 ;
    END
  END io_ibus_inst[24]
  PIN io_ibus_inst[25]
    DIRECTION OUTPUT TRISTATE ;
    USE SIGNAL ;
    PORT
      LAYER met3 ;
        RECT 0.000 882.680 4.000 883.280 ;
    END
  END io_ibus_inst[25]
  PIN io_ibus_inst[26]
    DIRECTION OUTPUT TRISTATE ;
    USE SIGNAL ;
    PORT
      LAYER met3 ;
        RECT 0.000 893.560 4.000 894.160 ;
    END
  END io_ibus_inst[26]
  PIN io_ibus_inst[27]
    DIRECTION OUTPUT TRISTATE ;
    USE SIGNAL ;
    PORT
      LAYER met3 ;
        RECT 0.000 905.120 4.000 905.720 ;
    END
  END io_ibus_inst[27]
  PIN io_ibus_inst[28]
    DIRECTION OUTPUT TRISTATE ;
    USE SIGNAL ;
    PORT
      LAYER met3 ;
        RECT 0.000 916.680 4.000 917.280 ;
    END
  END io_ibus_inst[28]
  PIN io_ibus_inst[29]
    DIRECTION OUTPUT TRISTATE ;
    USE SIGNAL ;
    PORT
      LAYER met3 ;
        RECT 0.000 927.560 4.000 928.160 ;
    END
  END io_ibus_inst[29]
  PIN io_ibus_inst[2]
    DIRECTION OUTPUT TRISTATE ;
    USE SIGNAL ;
    PORT
      LAYER met3 ;
        RECT 0.000 622.920 4.000 623.520 ;
    END
  END io_ibus_inst[2]
  PIN io_ibus_inst[30]
    DIRECTION OUTPUT TRISTATE ;
    USE SIGNAL ;
    PORT
      LAYER met3 ;
        RECT 0.000 939.120 4.000 939.720 ;
    END
  END io_ibus_inst[30]
  PIN io_ibus_inst[31]
    DIRECTION OUTPUT TRISTATE ;
    USE SIGNAL ;
    PORT
      LAYER met3 ;
        RECT 0.000 950.000 4.000 950.600 ;
    END
  END io_ibus_inst[31]
  PIN io_ibus_inst[3]
    DIRECTION OUTPUT TRISTATE ;
    USE SIGNAL ;
    PORT
      LAYER met3 ;
        RECT 0.000 634.480 4.000 635.080 ;
    END
  END io_ibus_inst[3]
  PIN io_ibus_inst[4]
    DIRECTION OUTPUT TRISTATE ;
    USE SIGNAL ;
    PORT
      LAYER met3 ;
        RECT 0.000 645.360 4.000 645.960 ;
    END
  END io_ibus_inst[4]
  PIN io_ibus_inst[5]
    DIRECTION OUTPUT TRISTATE ;
    USE SIGNAL ;
    PORT
      LAYER met3 ;
        RECT 0.000 656.920 4.000 657.520 ;
    END
  END io_ibus_inst[5]
  PIN io_ibus_inst[6]
    DIRECTION OUTPUT TRISTATE ;
    USE SIGNAL ;
    PORT
      LAYER met3 ;
        RECT 0.000 668.480 4.000 669.080 ;
    END
  END io_ibus_inst[6]
  PIN io_ibus_inst[7]
    DIRECTION OUTPUT TRISTATE ;
    USE SIGNAL ;
    PORT
      LAYER met3 ;
        RECT 0.000 679.360 4.000 679.960 ;
    END
  END io_ibus_inst[7]
  PIN io_ibus_inst[8]
    DIRECTION OUTPUT TRISTATE ;
    USE SIGNAL ;
    PORT
      LAYER met3 ;
        RECT 0.000 690.920 4.000 691.520 ;
    END
  END io_ibus_inst[8]
  PIN io_ibus_inst[9]
    DIRECTION OUTPUT TRISTATE ;
    USE SIGNAL ;
    PORT
      LAYER met3 ;
        RECT 0.000 701.800 4.000 702.400 ;
    END
  END io_ibus_inst[9]
  PIN io_ibus_valid
    DIRECTION OUTPUT TRISTATE ;
    USE SIGNAL ;
    PORT
      LAYER met3 ;
        RECT 0.000 588.920 4.000 589.520 ;
    END
  END io_ibus_valid
  PIN io_imem_io_addr[0]
    DIRECTION OUTPUT TRISTATE ;
    USE SIGNAL ;
    PORT
      LAYER met2 ;
        RECT 223.650 0.000 223.930 4.000 ;
    END
  END io_imem_io_addr[0]
  PIN io_imem_io_addr[1]
    DIRECTION OUTPUT TRISTATE ;
    USE SIGNAL ;
    PORT
      LAYER met3 ;
        RECT 1096.000 918.040 1100.000 918.640 ;
    END
  END io_imem_io_addr[1]
  PIN io_imem_io_addr[2]
    DIRECTION OUTPUT TRISTATE ;
    USE SIGNAL ;
    PORT
      LAYER met2 ;
        RECT 964.710 1096.000 964.990 1100.000 ;
    END
  END io_imem_io_addr[2]
  PIN io_imem_io_addr[3]
    DIRECTION OUTPUT TRISTATE ;
    USE SIGNAL ;
    PORT
      LAYER met3 ;
        RECT 1096.000 937.760 1100.000 938.360 ;
    END
  END io_imem_io_addr[3]
  PIN io_imem_io_addr[4]
    DIRECTION OUTPUT TRISTATE ;
    USE SIGNAL ;
    PORT
      LAYER met2 ;
        RECT 988.170 1096.000 988.450 1100.000 ;
    END
  END io_imem_io_addr[4]
  PIN io_imem_io_addr[5]
    DIRECTION OUTPUT TRISTATE ;
    USE SIGNAL ;
    PORT
      LAYER met3 ;
        RECT 1096.000 957.480 1100.000 958.080 ;
    END
  END io_imem_io_addr[5]
  PIN io_imem_io_addr[6]
    DIRECTION OUTPUT TRISTATE ;
    USE SIGNAL ;
    PORT
      LAYER met3 ;
        RECT 0.000 1006.440 4.000 1007.040 ;
    END
  END io_imem_io_addr[6]
  PIN io_imem_io_addr[7]
    DIRECTION OUTPUT TRISTATE ;
    USE SIGNAL ;
    PORT
      LAYER met2 ;
        RECT 468.370 0.000 468.650 4.000 ;
    END
  END io_imem_io_addr[7]
  PIN io_imem_io_addr[8]
    DIRECTION OUTPUT TRISTATE ;
    USE SIGNAL ;
    PORT
      LAYER met2 ;
        RECT 508.850 0.000 509.130 4.000 ;
    END
  END io_imem_io_addr[8]
  PIN io_imem_io_cs
    DIRECTION OUTPUT TRISTATE ;
    USE SIGNAL ;
    PORT
      LAYER met2 ;
        RECT 918.250 1096.000 918.530 1100.000 ;
    END
  END io_imem_io_cs
  PIN io_imem_io_rdata[0]
    DIRECTION INPUT ;
    USE SIGNAL ;
    PORT
      LAYER met3 ;
        RECT 1096.000 908.520 1100.000 909.120 ;
    END
  END io_imem_io_rdata[0]
  PIN io_imem_io_rdata[10]
    DIRECTION INPUT ;
    USE SIGNAL ;
    PORT
      LAYER met3 ;
        RECT 1096.000 986.720 1100.000 987.320 ;
    END
  END io_imem_io_rdata[10]
  PIN io_imem_io_rdata[11]
    DIRECTION INPUT ;
    USE SIGNAL ;
    PORT
      LAYER met2 ;
        RECT 631.210 0.000 631.490 4.000 ;
    END
  END io_imem_io_rdata[11]
  PIN io_imem_io_rdata[12]
    DIRECTION INPUT ;
    USE SIGNAL ;
    PORT
      LAYER met3 ;
        RECT 1096.000 996.920 1100.000 997.520 ;
    END
  END io_imem_io_rdata[12]
  PIN io_imem_io_rdata[13]
    DIRECTION INPUT ;
    USE SIGNAL ;
    PORT
      LAYER met3 ;
        RECT 0.000 1023.440 4.000 1024.040 ;
    END
  END io_imem_io_rdata[13]
  PIN io_imem_io_rdata[14]
    DIRECTION INPUT ;
    USE SIGNAL ;
    PORT
      LAYER met3 ;
        RECT 0.000 1035.000 4.000 1035.600 ;
    END
  END io_imem_io_rdata[14]
  PIN io_imem_io_rdata[15]
    DIRECTION INPUT ;
    USE SIGNAL ;
    PORT
      LAYER met3 ;
        RECT 1096.000 1006.440 1100.000 1007.040 ;
    END
  END io_imem_io_rdata[15]
  PIN io_imem_io_rdata[16]
    DIRECTION INPUT ;
    USE SIGNAL ;
    PORT
      LAYER met2 ;
        RECT 794.050 0.000 794.330 4.000 ;
    END
  END io_imem_io_rdata[16]
  PIN io_imem_io_rdata[17]
    DIRECTION INPUT ;
    USE SIGNAL ;
    PORT
      LAYER met3 ;
        RECT 0.000 1046.560 4.000 1047.160 ;
    END
  END io_imem_io_rdata[17]
  PIN io_imem_io_rdata[18]
    DIRECTION INPUT ;
    USE SIGNAL ;
    PORT
      LAYER met2 ;
        RECT 1058.550 1096.000 1058.830 1100.000 ;
    END
  END io_imem_io_rdata[18]
  PIN io_imem_io_rdata[19]
    DIRECTION INPUT ;
    USE SIGNAL ;
    PORT
      LAYER met3 ;
        RECT 0.000 1057.440 4.000 1058.040 ;
    END
  END io_imem_io_rdata[19]
  PIN io_imem_io_rdata[1]
    DIRECTION INPUT ;
    USE SIGNAL ;
    PORT
      LAYER met2 ;
        RECT 941.250 1096.000 941.530 1100.000 ;
    END
  END io_imem_io_rdata[1]
  PIN io_imem_io_rdata[20]
    DIRECTION INPUT ;
    USE SIGNAL ;
    PORT
      LAYER met3 ;
        RECT 1096.000 1015.960 1100.000 1016.560 ;
    END
  END io_imem_io_rdata[20]
  PIN io_imem_io_rdata[21]
    DIRECTION INPUT ;
    USE SIGNAL ;
    PORT
      LAYER met2 ;
        RECT 1082.010 1096.000 1082.290 1100.000 ;
    END
  END io_imem_io_rdata[21]
  PIN io_imem_io_rdata[22]
    DIRECTION INPUT ;
    USE SIGNAL ;
    PORT
      LAYER met3 ;
        RECT 0.000 1062.880 4.000 1063.480 ;
    END
  END io_imem_io_rdata[22]
  PIN io_imem_io_rdata[23]
    DIRECTION INPUT ;
    USE SIGNAL ;
    PORT
      LAYER met3 ;
        RECT 1096.000 1026.160 1100.000 1026.760 ;
    END
  END io_imem_io_rdata[23]
  PIN io_imem_io_rdata[24]
    DIRECTION INPUT ;
    USE SIGNAL ;
    PORT
      LAYER met2 ;
        RECT 997.830 0.000 998.110 4.000 ;
    END
  END io_imem_io_rdata[24]
  PIN io_imem_io_rdata[25]
    DIRECTION INPUT ;
    USE SIGNAL ;
    PORT
      LAYER met3 ;
        RECT 1096.000 1045.880 1100.000 1046.480 ;
    END
  END io_imem_io_rdata[25]
  PIN io_imem_io_rdata[26]
    DIRECTION INPUT ;
    USE SIGNAL ;
    PORT
      LAYER met2 ;
        RECT 1093.510 1096.000 1093.790 1100.000 ;
    END
  END io_imem_io_rdata[26]
  PIN io_imem_io_rdata[27]
    DIRECTION INPUT ;
    USE SIGNAL ;
    PORT
      LAYER met3 ;
        RECT 0.000 1079.880 4.000 1080.480 ;
    END
  END io_imem_io_rdata[27]
  PIN io_imem_io_rdata[28]
    DIRECTION INPUT ;
    USE SIGNAL ;
    PORT
      LAYER met3 ;
        RECT 0.000 1086.000 4.000 1086.600 ;
    END
  END io_imem_io_rdata[28]
  PIN io_imem_io_rdata[29]
    DIRECTION INPUT ;
    USE SIGNAL ;
    PORT
      LAYER met3 ;
        RECT 1096.000 1065.600 1100.000 1066.200 ;
    END
  END io_imem_io_rdata[29]
  PIN io_imem_io_rdata[2]
    DIRECTION INPUT ;
    USE SIGNAL ;
    PORT
      LAYER met2 ;
        RECT 976.670 1096.000 976.950 1100.000 ;
    END
  END io_imem_io_rdata[2]
  PIN io_imem_io_rdata[30]
    DIRECTION INPUT ;
    USE SIGNAL ;
    PORT
      LAYER met3 ;
        RECT 1096.000 1075.120 1100.000 1075.720 ;
    END
  END io_imem_io_rdata[30]
  PIN io_imem_io_rdata[31]
    DIRECTION INPUT ;
    USE SIGNAL ;
    PORT
      LAYER met3 ;
        RECT 1096.000 1094.840 1100.000 1095.440 ;
    END
  END io_imem_io_rdata[31]
  PIN io_imem_io_rdata[3]
    DIRECTION INPUT ;
    USE SIGNAL ;
    PORT
      LAYER met3 ;
        RECT 0.000 995.560 4.000 996.160 ;
    END
  END io_imem_io_rdata[3]
  PIN io_imem_io_rdata[4]
    DIRECTION INPUT ;
    USE SIGNAL ;
    PORT
      LAYER met2 ;
        RECT 1000.130 1096.000 1000.410 1100.000 ;
    END
  END io_imem_io_rdata[4]
  PIN io_imem_io_rdata[5]
    DIRECTION INPUT ;
    USE SIGNAL ;
    PORT
      LAYER met2 ;
        RECT 386.950 0.000 387.230 4.000 ;
    END
  END io_imem_io_rdata[5]
  PIN io_imem_io_rdata[6]
    DIRECTION INPUT ;
    USE SIGNAL ;
    PORT
      LAYER met2 ;
        RECT 427.430 0.000 427.710 4.000 ;
    END
  END io_imem_io_rdata[6]
  PIN io_imem_io_rdata[7]
    DIRECTION INPUT ;
    USE SIGNAL ;
    PORT
      LAYER met3 ;
        RECT 1096.000 967.000 1100.000 967.600 ;
    END
  END io_imem_io_rdata[7]
  PIN io_imem_io_rdata[8]
    DIRECTION INPUT ;
    USE SIGNAL ;
    PORT
      LAYER met2 ;
        RECT 1035.090 1096.000 1035.370 1100.000 ;
    END
  END io_imem_io_rdata[8]
  PIN io_imem_io_rdata[9]
    DIRECTION INPUT ;
    USE SIGNAL ;
    PORT
      LAYER met3 ;
        RECT 0.000 1018.000 4.000 1018.600 ;
    END
  END io_imem_io_rdata[9]
  PIN io_imem_io_st_type[0]
    DIRECTION OUTPUT TRISTATE ;
    USE SIGNAL ;
    PORT
      LAYER met3 ;
        RECT 0.000 984.000 4.000 984.600 ;
    END
  END io_imem_io_st_type[0]
  PIN io_imem_io_st_type[1]
    DIRECTION OUTPUT TRISTATE ;
    USE SIGNAL ;
    PORT
      LAYER met2 ;
        RECT 953.210 1096.000 953.490 1100.000 ;
    END
  END io_imem_io_st_type[1]
  PIN io_imem_io_st_type[2]
    DIRECTION OUTPUT TRISTATE ;
    USE SIGNAL ;
    PORT
      LAYER met2 ;
        RECT 305.070 0.000 305.350 4.000 ;
    END
  END io_imem_io_st_type[2]
  PIN io_imem_io_st_type[3]
    DIRECTION OUTPUT TRISTATE ;
    USE SIGNAL ;
    PORT
      LAYER met3 ;
        RECT 0.000 1001.000 4.000 1001.600 ;
    END
  END io_imem_io_st_type[3]
  PIN io_imem_io_wdata[0]
    DIRECTION OUTPUT TRISTATE ;
    USE SIGNAL ;
    PORT
      LAYER met2 ;
        RECT 264.590 0.000 264.870 4.000 ;
    END
  END io_imem_io_wdata[0]
  PIN io_imem_io_wdata[10]
    DIRECTION OUTPUT TRISTATE ;
    USE SIGNAL ;
    PORT
      LAYER met2 ;
        RECT 590.270 0.000 590.550 4.000 ;
    END
  END io_imem_io_wdata[10]
  PIN io_imem_io_wdata[11]
    DIRECTION OUTPUT TRISTATE ;
    USE SIGNAL ;
    PORT
      LAYER met2 ;
        RECT 671.690 0.000 671.970 4.000 ;
    END
  END io_imem_io_wdata[11]
  PIN io_imem_io_wdata[12]
    DIRECTION OUTPUT TRISTATE ;
    USE SIGNAL ;
    PORT
      LAYER met2 ;
        RECT 712.630 0.000 712.910 4.000 ;
    END
  END io_imem_io_wdata[12]
  PIN io_imem_io_wdata[13]
    DIRECTION OUTPUT TRISTATE ;
    USE SIGNAL ;
    PORT
      LAYER met3 ;
        RECT 0.000 1029.560 4.000 1030.160 ;
    END
  END io_imem_io_wdata[13]
  PIN io_imem_io_wdata[14]
    DIRECTION OUTPUT TRISTATE ;
    USE SIGNAL ;
    PORT
      LAYER met2 ;
        RECT 753.570 0.000 753.850 4.000 ;
    END
  END io_imem_io_wdata[14]
  PIN io_imem_io_wdata[15]
    DIRECTION OUTPUT TRISTATE ;
    USE SIGNAL ;
    PORT
      LAYER met3 ;
        RECT 0.000 1040.440 4.000 1041.040 ;
    END
  END io_imem_io_wdata[15]
  PIN io_imem_io_wdata[16]
    DIRECTION OUTPUT TRISTATE ;
    USE SIGNAL ;
    PORT
      LAYER met2 ;
        RECT 1046.590 1096.000 1046.870 1100.000 ;
    END
  END io_imem_io_wdata[16]
  PIN io_imem_io_wdata[17]
    DIRECTION OUTPUT TRISTATE ;
    USE SIGNAL ;
    PORT
      LAYER met2 ;
        RECT 834.990 0.000 835.270 4.000 ;
    END
  END io_imem_io_wdata[17]
  PIN io_imem_io_wdata[18]
    DIRECTION OUTPUT TRISTATE ;
    USE SIGNAL ;
    PORT
      LAYER met3 ;
        RECT 0.000 1052.000 4.000 1052.600 ;
    END
  END io_imem_io_wdata[18]
  PIN io_imem_io_wdata[19]
    DIRECTION OUTPUT TRISTATE ;
    USE SIGNAL ;
    PORT
      LAYER met2 ;
        RECT 1070.050 1096.000 1070.330 1100.000 ;
    END
  END io_imem_io_wdata[19]
  PIN io_imem_io_wdata[1]
    DIRECTION OUTPUT TRISTATE ;
    USE SIGNAL ;
    PORT
      LAYER met3 ;
        RECT 1096.000 927.560 1100.000 928.160 ;
    END
  END io_imem_io_wdata[1]
  PIN io_imem_io_wdata[20]
    DIRECTION OUTPUT TRISTATE ;
    USE SIGNAL ;
    PORT
      LAYER met2 ;
        RECT 875.470 0.000 875.750 4.000 ;
    END
  END io_imem_io_wdata[20]
  PIN io_imem_io_wdata[21]
    DIRECTION OUTPUT TRISTATE ;
    USE SIGNAL ;
    PORT
      LAYER met2 ;
        RECT 916.410 0.000 916.690 4.000 ;
    END
  END io_imem_io_wdata[21]
  PIN io_imem_io_wdata[22]
    DIRECTION OUTPUT TRISTATE ;
    USE SIGNAL ;
    PORT
      LAYER met2 ;
        RECT 956.890 0.000 957.170 4.000 ;
    END
  END io_imem_io_wdata[22]
  PIN io_imem_io_wdata[23]
    DIRECTION OUTPUT TRISTATE ;
    USE SIGNAL ;
    PORT
      LAYER met3 ;
        RECT 1096.000 1035.680 1100.000 1036.280 ;
    END
  END io_imem_io_wdata[23]
  PIN io_imem_io_wdata[24]
    DIRECTION OUTPUT TRISTATE ;
    USE SIGNAL ;
    PORT
      LAYER met2 ;
        RECT 1038.310 0.000 1038.590 4.000 ;
    END
  END io_imem_io_wdata[24]
  PIN io_imem_io_wdata[25]
    DIRECTION OUTPUT TRISTATE ;
    USE SIGNAL ;
    PORT
      LAYER met3 ;
        RECT 0.000 1069.000 4.000 1069.600 ;
    END
  END io_imem_io_wdata[25]
  PIN io_imem_io_wdata[26]
    DIRECTION OUTPUT TRISTATE ;
    USE SIGNAL ;
    PORT
      LAYER met3 ;
        RECT 0.000 1074.440 4.000 1075.040 ;
    END
  END io_imem_io_wdata[26]
  PIN io_imem_io_wdata[27]
    DIRECTION OUTPUT TRISTATE ;
    USE SIGNAL ;
    PORT
      LAYER met2 ;
        RECT 1079.250 0.000 1079.530 4.000 ;
    END
  END io_imem_io_wdata[27]
  PIN io_imem_io_wdata[28]
    DIRECTION OUTPUT TRISTATE ;
    USE SIGNAL ;
    PORT
      LAYER met3 ;
        RECT 1096.000 1055.400 1100.000 1056.000 ;
    END
  END io_imem_io_wdata[28]
  PIN io_imem_io_wdata[29]
    DIRECTION OUTPUT TRISTATE ;
    USE SIGNAL ;
    PORT
      LAYER met3 ;
        RECT 0.000 1091.440 4.000 1092.040 ;
    END
  END io_imem_io_wdata[29]
  PIN io_imem_io_wdata[2]
    DIRECTION OUTPUT TRISTATE ;
    USE SIGNAL ;
    PORT
      LAYER met3 ;
        RECT 0.000 990.120 4.000 990.720 ;
    END
  END io_imem_io_wdata[2]
  PIN io_imem_io_wdata[30]
    DIRECTION OUTPUT TRISTATE ;
    USE SIGNAL ;
    PORT
      LAYER met3 ;
        RECT 1096.000 1085.320 1100.000 1085.920 ;
    END
  END io_imem_io_wdata[30]
  PIN io_imem_io_wdata[31]
    DIRECTION OUTPUT TRISTATE ;
    USE SIGNAL ;
    PORT
      LAYER met3 ;
        RECT 0.000 1096.880 4.000 1097.480 ;
    END
  END io_imem_io_wdata[31]
  PIN io_imem_io_wdata[3]
    DIRECTION OUTPUT TRISTATE ;
    USE SIGNAL ;
    PORT
      LAYER met3 ;
        RECT 1096.000 947.280 1100.000 947.880 ;
    END
  END io_imem_io_wdata[3]
  PIN io_imem_io_wdata[4]
    DIRECTION OUTPUT TRISTATE ;
    USE SIGNAL ;
    PORT
      LAYER met2 ;
        RECT 346.010 0.000 346.290 4.000 ;
    END
  END io_imem_io_wdata[4]
  PIN io_imem_io_wdata[5]
    DIRECTION OUTPUT TRISTATE ;
    USE SIGNAL ;
    PORT
      LAYER met2 ;
        RECT 1011.630 1096.000 1011.910 1100.000 ;
    END
  END io_imem_io_wdata[5]
  PIN io_imem_io_wdata[6]
    DIRECTION OUTPUT TRISTATE ;
    USE SIGNAL ;
    PORT
      LAYER met3 ;
        RECT 0.000 1012.560 4.000 1013.160 ;
    END
  END io_imem_io_wdata[6]
  PIN io_imem_io_wdata[7]
    DIRECTION OUTPUT TRISTATE ;
    USE SIGNAL ;
    PORT
      LAYER met2 ;
        RECT 1023.130 1096.000 1023.410 1100.000 ;
    END
  END io_imem_io_wdata[7]
  PIN io_imem_io_wdata[8]
    DIRECTION OUTPUT TRISTATE ;
    USE SIGNAL ;
    PORT
      LAYER met3 ;
        RECT 1096.000 977.200 1100.000 977.800 ;
    END
  END io_imem_io_wdata[8]
  PIN io_imem_io_wdata[9]
    DIRECTION OUTPUT TRISTATE ;
    USE SIGNAL ;
    PORT
      LAYER met2 ;
        RECT 549.790 0.000 550.070 4.000 ;
    END
  END io_imem_io_wdata[9]
  PIN io_imem_io_wr_en
    DIRECTION OUTPUT TRISTATE ;
    USE SIGNAL ;
    PORT
      LAYER met2 ;
        RECT 929.750 1096.000 930.030 1100.000 ;
    END
  END io_imem_io_wr_en
  PIN io_motor_ack_i
    DIRECTION INPUT ;
    USE SIGNAL ;
    PORT
      LAYER met3 ;
        RECT 1096.000 4.800 1100.000 5.400 ;
    END
  END io_motor_ack_i
  PIN io_motor_addr_sel
    DIRECTION OUTPUT TRISTATE ;
    USE SIGNAL ;
    PORT
      LAYER met3 ;
        RECT 1096.000 14.320 1100.000 14.920 ;
    END
  END io_motor_addr_sel
  PIN io_motor_data_i[0]
    DIRECTION INPUT ;
    USE SIGNAL ;
    PORT
      LAYER met3 ;
        RECT 1096.000 23.840 1100.000 24.440 ;
    END
  END io_motor_data_i[0]
  PIN io_motor_data_i[10]
    DIRECTION INPUT ;
    USE SIGNAL ;
    PORT
      LAYER met3 ;
        RECT 1096.000 122.440 1100.000 123.040 ;
    END
  END io_motor_data_i[10]
  PIN io_motor_data_i[11]
    DIRECTION INPUT ;
    USE SIGNAL ;
    PORT
      LAYER met3 ;
        RECT 1096.000 131.960 1100.000 132.560 ;
    END
  END io_motor_data_i[11]
  PIN io_motor_data_i[12]
    DIRECTION INPUT ;
    USE SIGNAL ;
    PORT
      LAYER met3 ;
        RECT 1096.000 142.160 1100.000 142.760 ;
    END
  END io_motor_data_i[12]
  PIN io_motor_data_i[13]
    DIRECTION INPUT ;
    USE SIGNAL ;
    PORT
      LAYER met3 ;
        RECT 1096.000 151.680 1100.000 152.280 ;
    END
  END io_motor_data_i[13]
  PIN io_motor_data_i[14]
    DIRECTION INPUT ;
    USE SIGNAL ;
    PORT
      LAYER met3 ;
        RECT 1096.000 161.880 1100.000 162.480 ;
    END
  END io_motor_data_i[14]
  PIN io_motor_data_i[15]
    DIRECTION INPUT ;
    USE SIGNAL ;
    PORT
      LAYER met3 ;
        RECT 1096.000 171.400 1100.000 172.000 ;
    END
  END io_motor_data_i[15]
  PIN io_motor_data_i[16]
    DIRECTION INPUT ;
    USE SIGNAL ;
    PORT
      LAYER met3 ;
        RECT 1096.000 181.600 1100.000 182.200 ;
    END
  END io_motor_data_i[16]
  PIN io_motor_data_i[17]
    DIRECTION INPUT ;
    USE SIGNAL ;
    PORT
      LAYER met3 ;
        RECT 1096.000 191.120 1100.000 191.720 ;
    END
  END io_motor_data_i[17]
  PIN io_motor_data_i[18]
    DIRECTION INPUT ;
    USE SIGNAL ;
    PORT
      LAYER met3 ;
        RECT 1096.000 200.640 1100.000 201.240 ;
    END
  END io_motor_data_i[18]
  PIN io_motor_data_i[19]
    DIRECTION INPUT ;
    USE SIGNAL ;
    PORT
      LAYER met3 ;
        RECT 1096.000 210.840 1100.000 211.440 ;
    END
  END io_motor_data_i[19]
  PIN io_motor_data_i[1]
    DIRECTION INPUT ;
    USE SIGNAL ;
    PORT
      LAYER met3 ;
        RECT 1096.000 34.040 1100.000 34.640 ;
    END
  END io_motor_data_i[1]
  PIN io_motor_data_i[20]
    DIRECTION INPUT ;
    USE SIGNAL ;
    PORT
      LAYER met3 ;
        RECT 1096.000 220.360 1100.000 220.960 ;
    END
  END io_motor_data_i[20]
  PIN io_motor_data_i[21]
    DIRECTION INPUT ;
    USE SIGNAL ;
    PORT
      LAYER met3 ;
        RECT 1096.000 230.560 1100.000 231.160 ;
    END
  END io_motor_data_i[21]
  PIN io_motor_data_i[22]
    DIRECTION INPUT ;
    USE SIGNAL ;
    PORT
      LAYER met3 ;
        RECT 1096.000 240.080 1100.000 240.680 ;
    END
  END io_motor_data_i[22]
  PIN io_motor_data_i[23]
    DIRECTION INPUT ;
    USE SIGNAL ;
    PORT
      LAYER met3 ;
        RECT 1096.000 250.280 1100.000 250.880 ;
    END
  END io_motor_data_i[23]
  PIN io_motor_data_i[24]
    DIRECTION INPUT ;
    USE SIGNAL ;
    PORT
      LAYER met3 ;
        RECT 1096.000 259.800 1100.000 260.400 ;
    END
  END io_motor_data_i[24]
  PIN io_motor_data_i[25]
    DIRECTION INPUT ;
    USE SIGNAL ;
    PORT
      LAYER met3 ;
        RECT 1096.000 270.000 1100.000 270.600 ;
    END
  END io_motor_data_i[25]
  PIN io_motor_data_i[26]
    DIRECTION INPUT ;
    USE SIGNAL ;
    PORT
      LAYER met3 ;
        RECT 1096.000 279.520 1100.000 280.120 ;
    END
  END io_motor_data_i[26]
  PIN io_motor_data_i[27]
    DIRECTION INPUT ;
    USE SIGNAL ;
    PORT
      LAYER met3 ;
        RECT 1096.000 289.040 1100.000 289.640 ;
    END
  END io_motor_data_i[27]
  PIN io_motor_data_i[28]
    DIRECTION INPUT ;
    USE SIGNAL ;
    PORT
      LAYER met3 ;
        RECT 1096.000 299.240 1100.000 299.840 ;
    END
  END io_motor_data_i[28]
  PIN io_motor_data_i[29]
    DIRECTION INPUT ;
    USE SIGNAL ;
    PORT
      LAYER met3 ;
        RECT 1096.000 308.760 1100.000 309.360 ;
    END
  END io_motor_data_i[29]
  PIN io_motor_data_i[2]
    DIRECTION INPUT ;
    USE SIGNAL ;
    PORT
      LAYER met3 ;
        RECT 1096.000 43.560 1100.000 44.160 ;
    END
  END io_motor_data_i[2]
  PIN io_motor_data_i[30]
    DIRECTION INPUT ;
    USE SIGNAL ;
    PORT
      LAYER met3 ;
        RECT 1096.000 318.960 1100.000 319.560 ;
    END
  END io_motor_data_i[30]
  PIN io_motor_data_i[31]
    DIRECTION INPUT ;
    USE SIGNAL ;
    PORT
      LAYER met3 ;
        RECT 1096.000 328.480 1100.000 329.080 ;
    END
  END io_motor_data_i[31]
  PIN io_motor_data_i[3]
    DIRECTION INPUT ;
    USE SIGNAL ;
    PORT
      LAYER met3 ;
        RECT 1096.000 53.760 1100.000 54.360 ;
    END
  END io_motor_data_i[3]
  PIN io_motor_data_i[4]
    DIRECTION INPUT ;
    USE SIGNAL ;
    PORT
      LAYER met3 ;
        RECT 1096.000 63.280 1100.000 63.880 ;
    END
  END io_motor_data_i[4]
  PIN io_motor_data_i[5]
    DIRECTION INPUT ;
    USE SIGNAL ;
    PORT
      LAYER met3 ;
        RECT 1096.000 73.480 1100.000 74.080 ;
    END
  END io_motor_data_i[5]
  PIN io_motor_data_i[6]
    DIRECTION INPUT ;
    USE SIGNAL ;
    PORT
      LAYER met3 ;
        RECT 1096.000 83.000 1100.000 83.600 ;
    END
  END io_motor_data_i[6]
  PIN io_motor_data_i[7]
    DIRECTION INPUT ;
    USE SIGNAL ;
    PORT
      LAYER met3 ;
        RECT 1096.000 93.200 1100.000 93.800 ;
    END
  END io_motor_data_i[7]
  PIN io_motor_data_i[8]
    DIRECTION INPUT ;
    USE SIGNAL ;
    PORT
      LAYER met3 ;
        RECT 1096.000 102.720 1100.000 103.320 ;
    END
  END io_motor_data_i[8]
  PIN io_motor_data_i[9]
    DIRECTION INPUT ;
    USE SIGNAL ;
    PORT
      LAYER met3 ;
        RECT 1096.000 112.240 1100.000 112.840 ;
    END
  END io_motor_data_i[9]
  PIN io_spi_clk
    DIRECTION OUTPUT TRISTATE ;
    USE SIGNAL ;
    PORT
      LAYER met3 ;
        RECT 1096.000 869.080 1100.000 869.680 ;
    END
  END io_spi_clk
  PIN io_spi_clk_en
    DIRECTION OUTPUT TRISTATE ;
    USE SIGNAL ;
    PORT
      LAYER met3 ;
        RECT 0.000 967.000 4.000 967.600 ;
    END
  END io_spi_clk_en
  PIN io_spi_cs
    DIRECTION OUTPUT TRISTATE ;
    USE SIGNAL ;
    PORT
      LAYER met3 ;
        RECT 1096.000 878.600 1100.000 879.200 ;
    END
  END io_spi_cs
  PIN io_spi_cs_en
    DIRECTION OUTPUT TRISTATE ;
    USE SIGNAL ;
    PORT
      LAYER met2 ;
        RECT 183.170 0.000 183.450 4.000 ;
    END
  END io_spi_cs_en
  PIN io_spi_irq
    DIRECTION OUTPUT TRISTATE ;
    USE SIGNAL ;
    PORT
      LAYER met3 ;
        RECT 0.000 956.120 4.000 956.720 ;
    END
  END io_spi_irq
  PIN io_spi_miso
    DIRECTION INPUT ;
    USE SIGNAL ;
    PORT
      LAYER met2 ;
        RECT 101.750 0.000 102.030 4.000 ;
    END
  END io_spi_miso
  PIN io_spi_mosi
    DIRECTION OUTPUT TRISTATE ;
    USE SIGNAL ;
    PORT
      LAYER met3 ;
        RECT 1096.000 888.800 1100.000 889.400 ;
    END
  END io_spi_mosi
  PIN io_spi_mosi_en
    DIRECTION OUTPUT TRISTATE ;
    USE SIGNAL ;
    PORT
      LAYER met3 ;
        RECT 0.000 973.120 4.000 973.720 ;
    END
  END io_spi_mosi_en
  PIN io_uart_irq
    DIRECTION OUTPUT TRISTATE ;
    USE SIGNAL ;
    PORT
      LAYER met3 ;
        RECT 0.000 961.560 4.000 962.160 ;
    END
  END io_uart_irq
  PIN io_uart_rx
    DIRECTION INPUT ;
    USE SIGNAL ;
    PORT
      LAYER met2 ;
        RECT 142.230 0.000 142.510 4.000 ;
    END
  END io_uart_rx
  PIN io_uart_tx
    DIRECTION OUTPUT TRISTATE ;
    USE SIGNAL ;
    PORT
      LAYER met3 ;
        RECT 1096.000 898.320 1100.000 898.920 ;
    END
  END io_uart_tx
  PIN io_uart_txen
    DIRECTION OUTPUT TRISTATE ;
    USE SIGNAL ;
    PORT
      LAYER met3 ;
        RECT 0.000 978.560 4.000 979.160 ;
    END
  END io_uart_txen
  PIN io_wbm_m2s_addr[0]
    DIRECTION OUTPUT TRISTATE ;
    USE SIGNAL ;
    PORT
      LAYER met3 ;
        RECT 1096.000 358.400 1100.000 359.000 ;
    END
  END io_wbm_m2s_addr[0]
  PIN io_wbm_m2s_addr[10]
    DIRECTION OUTPUT TRISTATE ;
    USE SIGNAL ;
    PORT
      LAYER met3 ;
        RECT 1096.000 593.680 1100.000 594.280 ;
    END
  END io_wbm_m2s_addr[10]
  PIN io_wbm_m2s_addr[11]
    DIRECTION OUTPUT TRISTATE ;
    USE SIGNAL ;
    PORT
      LAYER met3 ;
        RECT 1096.000 613.400 1100.000 614.000 ;
    END
  END io_wbm_m2s_addr[11]
  PIN io_wbm_m2s_addr[12]
    DIRECTION OUTPUT TRISTATE ;
    USE SIGNAL ;
    PORT
      LAYER met3 ;
        RECT 1096.000 633.120 1100.000 633.720 ;
    END
  END io_wbm_m2s_addr[12]
  PIN io_wbm_m2s_addr[13]
    DIRECTION OUTPUT TRISTATE ;
    USE SIGNAL ;
    PORT
      LAYER met3 ;
        RECT 1096.000 652.840 1100.000 653.440 ;
    END
  END io_wbm_m2s_addr[13]
  PIN io_wbm_m2s_addr[14]
    DIRECTION OUTPUT TRISTATE ;
    USE SIGNAL ;
    PORT
      LAYER met3 ;
        RECT 1096.000 672.560 1100.000 673.160 ;
    END
  END io_wbm_m2s_addr[14]
  PIN io_wbm_m2s_addr[15]
    DIRECTION OUTPUT TRISTATE ;
    USE SIGNAL ;
    PORT
      LAYER met3 ;
        RECT 1096.000 692.280 1100.000 692.880 ;
    END
  END io_wbm_m2s_addr[15]
  PIN io_wbm_m2s_addr[1]
    DIRECTION OUTPUT TRISTATE ;
    USE SIGNAL ;
    PORT
      LAYER met3 ;
        RECT 1096.000 387.640 1100.000 388.240 ;
    END
  END io_wbm_m2s_addr[1]
  PIN io_wbm_m2s_addr[2]
    DIRECTION OUTPUT TRISTATE ;
    USE SIGNAL ;
    PORT
      LAYER met3 ;
        RECT 1096.000 416.880 1100.000 417.480 ;
    END
  END io_wbm_m2s_addr[2]
  PIN io_wbm_m2s_addr[3]
    DIRECTION OUTPUT TRISTATE ;
    USE SIGNAL ;
    PORT
      LAYER met3 ;
        RECT 1096.000 446.800 1100.000 447.400 ;
    END
  END io_wbm_m2s_addr[3]
  PIN io_wbm_m2s_addr[4]
    DIRECTION OUTPUT TRISTATE ;
    USE SIGNAL ;
    PORT
      LAYER met3 ;
        RECT 1096.000 476.040 1100.000 476.640 ;
    END
  END io_wbm_m2s_addr[4]
  PIN io_wbm_m2s_addr[5]
    DIRECTION OUTPUT TRISTATE ;
    USE SIGNAL ;
    PORT
      LAYER met3 ;
        RECT 1096.000 495.760 1100.000 496.360 ;
    END
  END io_wbm_m2s_addr[5]
  PIN io_wbm_m2s_addr[6]
    DIRECTION OUTPUT TRISTATE ;
    USE SIGNAL ;
    PORT
      LAYER met3 ;
        RECT 1096.000 515.480 1100.000 516.080 ;
    END
  END io_wbm_m2s_addr[6]
  PIN io_wbm_m2s_addr[7]
    DIRECTION OUTPUT TRISTATE ;
    USE SIGNAL ;
    PORT
      LAYER met3 ;
        RECT 1096.000 535.200 1100.000 535.800 ;
    END
  END io_wbm_m2s_addr[7]
  PIN io_wbm_m2s_addr[8]
    DIRECTION OUTPUT TRISTATE ;
    USE SIGNAL ;
    PORT
      LAYER met3 ;
        RECT 1096.000 554.920 1100.000 555.520 ;
    END
  END io_wbm_m2s_addr[8]
  PIN io_wbm_m2s_addr[9]
    DIRECTION OUTPUT TRISTATE ;
    USE SIGNAL ;
    PORT
      LAYER met3 ;
        RECT 1096.000 573.960 1100.000 574.560 ;
    END
  END io_wbm_m2s_addr[9]
  PIN io_wbm_m2s_data[0]
    DIRECTION OUTPUT TRISTATE ;
    USE SIGNAL ;
    PORT
      LAYER met3 ;
        RECT 1096.000 367.920 1100.000 368.520 ;
    END
  END io_wbm_m2s_data[0]
  PIN io_wbm_m2s_data[10]
    DIRECTION OUTPUT TRISTATE ;
    USE SIGNAL ;
    PORT
      LAYER met3 ;
        RECT 1096.000 603.880 1100.000 604.480 ;
    END
  END io_wbm_m2s_data[10]
  PIN io_wbm_m2s_data[11]
    DIRECTION OUTPUT TRISTATE ;
    USE SIGNAL ;
    PORT
      LAYER met3 ;
        RECT 1096.000 623.600 1100.000 624.200 ;
    END
  END io_wbm_m2s_data[11]
  PIN io_wbm_m2s_data[12]
    DIRECTION OUTPUT TRISTATE ;
    USE SIGNAL ;
    PORT
      LAYER met3 ;
        RECT 1096.000 643.320 1100.000 643.920 ;
    END
  END io_wbm_m2s_data[12]
  PIN io_wbm_m2s_data[13]
    DIRECTION OUTPUT TRISTATE ;
    USE SIGNAL ;
    PORT
      LAYER met3 ;
        RECT 1096.000 662.360 1100.000 662.960 ;
    END
  END io_wbm_m2s_data[13]
  PIN io_wbm_m2s_data[14]
    DIRECTION OUTPUT TRISTATE ;
    USE SIGNAL ;
    PORT
      LAYER met3 ;
        RECT 1096.000 682.080 1100.000 682.680 ;
    END
  END io_wbm_m2s_data[14]
  PIN io_wbm_m2s_data[15]
    DIRECTION OUTPUT TRISTATE ;
    USE SIGNAL ;
    PORT
      LAYER met3 ;
        RECT 1096.000 701.800 1100.000 702.400 ;
    END
  END io_wbm_m2s_data[15]
  PIN io_wbm_m2s_data[16]
    DIRECTION OUTPUT TRISTATE ;
    USE SIGNAL ;
    PORT
      LAYER met3 ;
        RECT 1096.000 712.000 1100.000 712.600 ;
    END
  END io_wbm_m2s_data[16]
  PIN io_wbm_m2s_data[17]
    DIRECTION OUTPUT TRISTATE ;
    USE SIGNAL ;
    PORT
      LAYER met3 ;
        RECT 1096.000 721.520 1100.000 722.120 ;
    END
  END io_wbm_m2s_data[17]
  PIN io_wbm_m2s_data[18]
    DIRECTION OUTPUT TRISTATE ;
    USE SIGNAL ;
    PORT
      LAYER met3 ;
        RECT 1096.000 731.720 1100.000 732.320 ;
    END
  END io_wbm_m2s_data[18]
  PIN io_wbm_m2s_data[19]
    DIRECTION OUTPUT TRISTATE ;
    USE SIGNAL ;
    PORT
      LAYER met3 ;
        RECT 1096.000 741.240 1100.000 741.840 ;
    END
  END io_wbm_m2s_data[19]
  PIN io_wbm_m2s_data[1]
    DIRECTION OUTPUT TRISTATE ;
    USE SIGNAL ;
    PORT
      LAYER met3 ;
        RECT 1096.000 397.160 1100.000 397.760 ;
    END
  END io_wbm_m2s_data[1]
  PIN io_wbm_m2s_data[20]
    DIRECTION OUTPUT TRISTATE ;
    USE SIGNAL ;
    PORT
      LAYER met3 ;
        RECT 1096.000 750.760 1100.000 751.360 ;
    END
  END io_wbm_m2s_data[20]
  PIN io_wbm_m2s_data[21]
    DIRECTION OUTPUT TRISTATE ;
    USE SIGNAL ;
    PORT
      LAYER met3 ;
        RECT 1096.000 760.960 1100.000 761.560 ;
    END
  END io_wbm_m2s_data[21]
  PIN io_wbm_m2s_data[22]
    DIRECTION OUTPUT TRISTATE ;
    USE SIGNAL ;
    PORT
      LAYER met3 ;
        RECT 1096.000 770.480 1100.000 771.080 ;
    END
  END io_wbm_m2s_data[22]
  PIN io_wbm_m2s_data[23]
    DIRECTION OUTPUT TRISTATE ;
    USE SIGNAL ;
    PORT
      LAYER met3 ;
        RECT 1096.000 780.680 1100.000 781.280 ;
    END
  END io_wbm_m2s_data[23]
  PIN io_wbm_m2s_data[24]
    DIRECTION OUTPUT TRISTATE ;
    USE SIGNAL ;
    PORT
      LAYER met3 ;
        RECT 1096.000 790.200 1100.000 790.800 ;
    END
  END io_wbm_m2s_data[24]
  PIN io_wbm_m2s_data[25]
    DIRECTION OUTPUT TRISTATE ;
    USE SIGNAL ;
    PORT
      LAYER met3 ;
        RECT 1096.000 800.400 1100.000 801.000 ;
    END
  END io_wbm_m2s_data[25]
  PIN io_wbm_m2s_data[26]
    DIRECTION OUTPUT TRISTATE ;
    USE SIGNAL ;
    PORT
      LAYER met3 ;
        RECT 1096.000 809.920 1100.000 810.520 ;
    END
  END io_wbm_m2s_data[26]
  PIN io_wbm_m2s_data[27]
    DIRECTION OUTPUT TRISTATE ;
    USE SIGNAL ;
    PORT
      LAYER met3 ;
        RECT 1096.000 820.120 1100.000 820.720 ;
    END
  END io_wbm_m2s_data[27]
  PIN io_wbm_m2s_data[28]
    DIRECTION OUTPUT TRISTATE ;
    USE SIGNAL ;
    PORT
      LAYER met3 ;
        RECT 1096.000 829.640 1100.000 830.240 ;
    END
  END io_wbm_m2s_data[28]
  PIN io_wbm_m2s_data[29]
    DIRECTION OUTPUT TRISTATE ;
    USE SIGNAL ;
    PORT
      LAYER met3 ;
        RECT 1096.000 839.160 1100.000 839.760 ;
    END
  END io_wbm_m2s_data[29]
  PIN io_wbm_m2s_data[2]
    DIRECTION OUTPUT TRISTATE ;
    USE SIGNAL ;
    PORT
      LAYER met3 ;
        RECT 1096.000 427.080 1100.000 427.680 ;
    END
  END io_wbm_m2s_data[2]
  PIN io_wbm_m2s_data[30]
    DIRECTION OUTPUT TRISTATE ;
    USE SIGNAL ;
    PORT
      LAYER met3 ;
        RECT 1096.000 849.360 1100.000 849.960 ;
    END
  END io_wbm_m2s_data[30]
  PIN io_wbm_m2s_data[31]
    DIRECTION OUTPUT TRISTATE ;
    USE SIGNAL ;
    PORT
      LAYER met3 ;
        RECT 1096.000 858.880 1100.000 859.480 ;
    END
  END io_wbm_m2s_data[31]
  PIN io_wbm_m2s_data[3]
    DIRECTION OUTPUT TRISTATE ;
    USE SIGNAL ;
    PORT
      LAYER met3 ;
        RECT 1096.000 456.320 1100.000 456.920 ;
    END
  END io_wbm_m2s_data[3]
  PIN io_wbm_m2s_data[4]
    DIRECTION OUTPUT TRISTATE ;
    USE SIGNAL ;
    PORT
      LAYER met3 ;
        RECT 1096.000 485.560 1100.000 486.160 ;
    END
  END io_wbm_m2s_data[4]
  PIN io_wbm_m2s_data[5]
    DIRECTION OUTPUT TRISTATE ;
    USE SIGNAL ;
    PORT
      LAYER met3 ;
        RECT 1096.000 505.280 1100.000 505.880 ;
    END
  END io_wbm_m2s_data[5]
  PIN io_wbm_m2s_data[6]
    DIRECTION OUTPUT TRISTATE ;
    USE SIGNAL ;
    PORT
      LAYER met3 ;
        RECT 1096.000 525.000 1100.000 525.600 ;
    END
  END io_wbm_m2s_data[6]
  PIN io_wbm_m2s_data[7]
    DIRECTION OUTPUT TRISTATE ;
    USE SIGNAL ;
    PORT
      LAYER met3 ;
        RECT 1096.000 544.720 1100.000 545.320 ;
    END
  END io_wbm_m2s_data[7]
  PIN io_wbm_m2s_data[8]
    DIRECTION OUTPUT TRISTATE ;
    USE SIGNAL ;
    PORT
      LAYER met3 ;
        RECT 1096.000 564.440 1100.000 565.040 ;
    END
  END io_wbm_m2s_data[8]
  PIN io_wbm_m2s_data[9]
    DIRECTION OUTPUT TRISTATE ;
    USE SIGNAL ;
    PORT
      LAYER met3 ;
        RECT 1096.000 584.160 1100.000 584.760 ;
    END
  END io_wbm_m2s_data[9]
  PIN io_wbm_m2s_sel[0]
    DIRECTION OUTPUT TRISTATE ;
    USE SIGNAL ;
    PORT
      LAYER met3 ;
        RECT 1096.000 377.440 1100.000 378.040 ;
    END
  END io_wbm_m2s_sel[0]
  PIN io_wbm_m2s_sel[1]
    DIRECTION OUTPUT TRISTATE ;
    USE SIGNAL ;
    PORT
      LAYER met3 ;
        RECT 1096.000 407.360 1100.000 407.960 ;
    END
  END io_wbm_m2s_sel[1]
  PIN io_wbm_m2s_sel[2]
    DIRECTION OUTPUT TRISTATE ;
    USE SIGNAL ;
    PORT
      LAYER met3 ;
        RECT 1096.000 436.600 1100.000 437.200 ;
    END
  END io_wbm_m2s_sel[2]
  PIN io_wbm_m2s_sel[3]
    DIRECTION OUTPUT TRISTATE ;
    USE SIGNAL ;
    PORT
      LAYER met3 ;
        RECT 1096.000 465.840 1100.000 466.440 ;
    END
  END io_wbm_m2s_sel[3]
  PIN io_wbm_m2s_stb
    DIRECTION OUTPUT TRISTATE ;
    USE SIGNAL ;
    PORT
      LAYER met3 ;
        RECT 1096.000 338.680 1100.000 339.280 ;
    END
  END io_wbm_m2s_stb
  PIN io_wbm_m2s_we
    DIRECTION OUTPUT TRISTATE ;
    USE SIGNAL ;
    PORT
      LAYER met3 ;
        RECT 1096.000 348.200 1100.000 348.800 ;
    END
  END io_wbm_m2s_we
  PIN reset
    DIRECTION INPUT ;
    USE SIGNAL ;
    PORT
      LAYER met2 ;
        RECT 60.810 0.000 61.090 4.000 ;
    END
  END reset
  PIN vccd1
    DIRECTION INPUT ;
    USE POWER ;
    PORT
      LAYER met4 ;
        RECT 21.040 10.640 22.640 1088.240 ;
    END
    PORT
      LAYER met4 ;
        RECT 174.640 10.640 176.240 1088.240 ;
    END
    PORT
      LAYER met4 ;
        RECT 328.240 10.640 329.840 1088.240 ;
    END
    PORT
      LAYER met4 ;
        RECT 481.840 10.640 483.440 1088.240 ;
    END
    PORT
      LAYER met4 ;
        RECT 635.440 10.640 637.040 1088.240 ;
    END
    PORT
      LAYER met4 ;
        RECT 789.040 10.640 790.640 1088.240 ;
    END
    PORT
      LAYER met4 ;
        RECT 942.640 10.640 944.240 1088.240 ;
    END
  END vccd1
  PIN vssd1
    DIRECTION INPUT ;
    USE GROUND ;
    PORT
      LAYER met4 ;
        RECT 97.840 10.640 99.440 1088.240 ;
    END
    PORT
      LAYER met4 ;
        RECT 251.440 10.640 253.040 1088.240 ;
    END
    PORT
      LAYER met4 ;
        RECT 405.040 10.640 406.640 1088.240 ;
    END
    PORT
      LAYER met4 ;
        RECT 558.640 10.640 560.240 1088.240 ;
    END
    PORT
      LAYER met4 ;
        RECT 712.240 10.640 713.840 1088.240 ;
    END
    PORT
      LAYER met4 ;
        RECT 865.840 10.640 867.440 1088.240 ;
    END
    PORT
      LAYER met4 ;
        RECT 1019.440 10.640 1021.040 1088.240 ;
    END
  END vssd1
  OBS
      LAYER li1 ;
        RECT 5.520 10.795 1094.340 1088.085 ;
      LAYER met1 ;
        RECT 0.070 10.640 1094.340 1088.980 ;
      LAYER met2 ;
        RECT 0.090 1095.720 5.330 1097.365 ;
        RECT 6.170 1095.720 16.830 1097.365 ;
        RECT 17.670 1095.720 28.330 1097.365 ;
        RECT 29.170 1095.720 40.290 1097.365 ;
        RECT 41.130 1095.720 51.790 1097.365 ;
        RECT 52.630 1095.720 63.750 1097.365 ;
        RECT 64.590 1095.720 75.250 1097.365 ;
        RECT 76.090 1095.720 87.210 1097.365 ;
        RECT 88.050 1095.720 98.710 1097.365 ;
        RECT 99.550 1095.720 110.210 1097.365 ;
        RECT 111.050 1095.720 122.170 1097.365 ;
        RECT 123.010 1095.720 133.670 1097.365 ;
        RECT 134.510 1095.720 145.630 1097.365 ;
        RECT 146.470 1095.720 157.130 1097.365 ;
        RECT 157.970 1095.720 169.090 1097.365 ;
        RECT 169.930 1095.720 180.590 1097.365 ;
        RECT 181.430 1095.720 192.090 1097.365 ;
        RECT 192.930 1095.720 204.050 1097.365 ;
        RECT 204.890 1095.720 215.550 1097.365 ;
        RECT 216.390 1095.720 227.510 1097.365 ;
        RECT 228.350 1095.720 239.010 1097.365 ;
        RECT 239.850 1095.720 250.970 1097.365 ;
        RECT 251.810 1095.720 262.470 1097.365 ;
        RECT 263.310 1095.720 274.430 1097.365 ;
        RECT 275.270 1095.720 285.930 1097.365 ;
        RECT 286.770 1095.720 297.430 1097.365 ;
        RECT 298.270 1095.720 309.390 1097.365 ;
        RECT 310.230 1095.720 320.890 1097.365 ;
        RECT 321.730 1095.720 332.850 1097.365 ;
        RECT 333.690 1095.720 344.350 1097.365 ;
        RECT 345.190 1095.720 356.310 1097.365 ;
        RECT 357.150 1095.720 367.810 1097.365 ;
        RECT 368.650 1095.720 379.310 1097.365 ;
        RECT 380.150 1095.720 391.270 1097.365 ;
        RECT 392.110 1095.720 402.770 1097.365 ;
        RECT 403.610 1095.720 414.730 1097.365 ;
        RECT 415.570 1095.720 426.230 1097.365 ;
        RECT 427.070 1095.720 438.190 1097.365 ;
        RECT 439.030 1095.720 449.690 1097.365 ;
        RECT 450.530 1095.720 461.650 1097.365 ;
        RECT 462.490 1095.720 473.150 1097.365 ;
        RECT 473.990 1095.720 484.650 1097.365 ;
        RECT 485.490 1095.720 496.610 1097.365 ;
        RECT 497.450 1095.720 508.110 1097.365 ;
        RECT 508.950 1095.720 520.070 1097.365 ;
        RECT 520.910 1095.720 531.570 1097.365 ;
        RECT 532.410 1095.720 543.530 1097.365 ;
        RECT 544.370 1095.720 555.030 1097.365 ;
        RECT 555.870 1095.720 566.530 1097.365 ;
        RECT 567.370 1095.720 578.490 1097.365 ;
        RECT 579.330 1095.720 589.990 1097.365 ;
        RECT 590.830 1095.720 601.950 1097.365 ;
        RECT 602.790 1095.720 613.450 1097.365 ;
        RECT 614.290 1095.720 625.410 1097.365 ;
        RECT 626.250 1095.720 636.910 1097.365 ;
        RECT 637.750 1095.720 648.410 1097.365 ;
        RECT 649.250 1095.720 660.370 1097.365 ;
        RECT 661.210 1095.720 671.870 1097.365 ;
        RECT 672.710 1095.720 683.830 1097.365 ;
        RECT 684.670 1095.720 695.330 1097.365 ;
        RECT 696.170 1095.720 707.290 1097.365 ;
        RECT 708.130 1095.720 718.790 1097.365 ;
        RECT 719.630 1095.720 730.750 1097.365 ;
        RECT 731.590 1095.720 742.250 1097.365 ;
        RECT 743.090 1095.720 753.750 1097.365 ;
        RECT 754.590 1095.720 765.710 1097.365 ;
        RECT 766.550 1095.720 777.210 1097.365 ;
        RECT 778.050 1095.720 789.170 1097.365 ;
        RECT 790.010 1095.720 800.670 1097.365 ;
        RECT 801.510 1095.720 812.630 1097.365 ;
        RECT 813.470 1095.720 824.130 1097.365 ;
        RECT 824.970 1095.720 835.630 1097.365 ;
        RECT 836.470 1095.720 847.590 1097.365 ;
        RECT 848.430 1095.720 859.090 1097.365 ;
        RECT 859.930 1095.720 871.050 1097.365 ;
        RECT 871.890 1095.720 882.550 1097.365 ;
        RECT 883.390 1095.720 894.510 1097.365 ;
        RECT 895.350 1095.720 906.010 1097.365 ;
        RECT 906.850 1095.720 917.970 1097.365 ;
        RECT 918.810 1095.720 929.470 1097.365 ;
        RECT 930.310 1095.720 940.970 1097.365 ;
        RECT 941.810 1095.720 952.930 1097.365 ;
        RECT 953.770 1095.720 964.430 1097.365 ;
        RECT 965.270 1095.720 976.390 1097.365 ;
        RECT 977.230 1095.720 987.890 1097.365 ;
        RECT 988.730 1095.720 999.850 1097.365 ;
        RECT 1000.690 1095.720 1011.350 1097.365 ;
        RECT 1012.190 1095.720 1022.850 1097.365 ;
        RECT 1023.690 1095.720 1034.810 1097.365 ;
        RECT 1035.650 1095.720 1046.310 1097.365 ;
        RECT 1047.150 1095.720 1058.270 1097.365 ;
        RECT 1059.110 1095.720 1069.770 1097.365 ;
        RECT 1070.610 1095.720 1081.730 1097.365 ;
        RECT 1082.570 1095.720 1093.230 1097.365 ;
        RECT 0.090 4.280 1093.780 1095.720 ;
        RECT 0.090 2.875 20.050 4.280 ;
        RECT 20.890 2.875 60.530 4.280 ;
        RECT 61.370 2.875 101.470 4.280 ;
        RECT 102.310 2.875 141.950 4.280 ;
        RECT 142.790 2.875 182.890 4.280 ;
        RECT 183.730 2.875 223.370 4.280 ;
        RECT 224.210 2.875 264.310 4.280 ;
        RECT 265.150 2.875 304.790 4.280 ;
        RECT 305.630 2.875 345.730 4.280 ;
        RECT 346.570 2.875 386.670 4.280 ;
        RECT 387.510 2.875 427.150 4.280 ;
        RECT 427.990 2.875 468.090 4.280 ;
        RECT 468.930 2.875 508.570 4.280 ;
        RECT 509.410 2.875 549.510 4.280 ;
        RECT 550.350 2.875 589.990 4.280 ;
        RECT 590.830 2.875 630.930 4.280 ;
        RECT 631.770 2.875 671.410 4.280 ;
        RECT 672.250 2.875 712.350 4.280 ;
        RECT 713.190 2.875 753.290 4.280 ;
        RECT 754.130 2.875 793.770 4.280 ;
        RECT 794.610 2.875 834.710 4.280 ;
        RECT 835.550 2.875 875.190 4.280 ;
        RECT 876.030 2.875 916.130 4.280 ;
        RECT 916.970 2.875 956.610 4.280 ;
        RECT 957.450 2.875 997.550 4.280 ;
        RECT 998.390 2.875 1038.030 4.280 ;
        RECT 1038.870 2.875 1078.970 4.280 ;
        RECT 1079.810 2.875 1093.780 4.280 ;
      LAYER met3 ;
        RECT 4.400 1096.480 1096.000 1097.345 ;
        RECT 0.065 1095.840 1096.000 1096.480 ;
        RECT 0.065 1094.440 1095.600 1095.840 ;
        RECT 0.065 1092.440 1096.000 1094.440 ;
        RECT 4.400 1091.040 1096.000 1092.440 ;
        RECT 0.065 1087.000 1096.000 1091.040 ;
        RECT 4.400 1086.320 1096.000 1087.000 ;
        RECT 4.400 1085.600 1095.600 1086.320 ;
        RECT 0.065 1084.920 1095.600 1085.600 ;
        RECT 0.065 1080.880 1096.000 1084.920 ;
        RECT 4.400 1079.480 1096.000 1080.880 ;
        RECT 0.065 1076.120 1096.000 1079.480 ;
        RECT 0.065 1075.440 1095.600 1076.120 ;
        RECT 4.400 1074.720 1095.600 1075.440 ;
        RECT 4.400 1074.040 1096.000 1074.720 ;
        RECT 0.065 1070.000 1096.000 1074.040 ;
        RECT 4.400 1068.600 1096.000 1070.000 ;
        RECT 0.065 1066.600 1096.000 1068.600 ;
        RECT 0.065 1065.200 1095.600 1066.600 ;
        RECT 0.065 1063.880 1096.000 1065.200 ;
        RECT 4.400 1062.480 1096.000 1063.880 ;
        RECT 0.065 1058.440 1096.000 1062.480 ;
        RECT 4.400 1057.040 1096.000 1058.440 ;
        RECT 0.065 1056.400 1096.000 1057.040 ;
        RECT 0.065 1055.000 1095.600 1056.400 ;
        RECT 0.065 1053.000 1096.000 1055.000 ;
        RECT 4.400 1051.600 1096.000 1053.000 ;
        RECT 0.065 1047.560 1096.000 1051.600 ;
        RECT 4.400 1046.880 1096.000 1047.560 ;
        RECT 4.400 1046.160 1095.600 1046.880 ;
        RECT 0.065 1045.480 1095.600 1046.160 ;
        RECT 0.065 1041.440 1096.000 1045.480 ;
        RECT 4.400 1040.040 1096.000 1041.440 ;
        RECT 0.065 1036.680 1096.000 1040.040 ;
        RECT 0.065 1036.000 1095.600 1036.680 ;
        RECT 4.400 1035.280 1095.600 1036.000 ;
        RECT 4.400 1034.600 1096.000 1035.280 ;
        RECT 0.065 1030.560 1096.000 1034.600 ;
        RECT 4.400 1029.160 1096.000 1030.560 ;
        RECT 0.065 1027.160 1096.000 1029.160 ;
        RECT 0.065 1025.760 1095.600 1027.160 ;
        RECT 0.065 1024.440 1096.000 1025.760 ;
        RECT 4.400 1023.040 1096.000 1024.440 ;
        RECT 0.065 1019.000 1096.000 1023.040 ;
        RECT 4.400 1017.600 1096.000 1019.000 ;
        RECT 0.065 1016.960 1096.000 1017.600 ;
        RECT 0.065 1015.560 1095.600 1016.960 ;
        RECT 0.065 1013.560 1096.000 1015.560 ;
        RECT 4.400 1012.160 1096.000 1013.560 ;
        RECT 0.065 1007.440 1096.000 1012.160 ;
        RECT 4.400 1006.040 1095.600 1007.440 ;
        RECT 0.065 1002.000 1096.000 1006.040 ;
        RECT 4.400 1000.600 1096.000 1002.000 ;
        RECT 0.065 997.920 1096.000 1000.600 ;
        RECT 0.065 996.560 1095.600 997.920 ;
        RECT 4.400 996.520 1095.600 996.560 ;
        RECT 4.400 995.160 1096.000 996.520 ;
        RECT 0.065 991.120 1096.000 995.160 ;
        RECT 4.400 989.720 1096.000 991.120 ;
        RECT 0.065 987.720 1096.000 989.720 ;
        RECT 0.065 986.320 1095.600 987.720 ;
        RECT 0.065 985.000 1096.000 986.320 ;
        RECT 4.400 983.600 1096.000 985.000 ;
        RECT 0.065 979.560 1096.000 983.600 ;
        RECT 4.400 978.200 1096.000 979.560 ;
        RECT 4.400 978.160 1095.600 978.200 ;
        RECT 0.065 976.800 1095.600 978.160 ;
        RECT 0.065 974.120 1096.000 976.800 ;
        RECT 4.400 972.720 1096.000 974.120 ;
        RECT 0.065 968.000 1096.000 972.720 ;
        RECT 4.400 966.600 1095.600 968.000 ;
        RECT 0.065 962.560 1096.000 966.600 ;
        RECT 4.400 961.160 1096.000 962.560 ;
        RECT 0.065 958.480 1096.000 961.160 ;
        RECT 0.065 957.120 1095.600 958.480 ;
        RECT 4.400 957.080 1095.600 957.120 ;
        RECT 4.400 955.720 1096.000 957.080 ;
        RECT 0.065 951.000 1096.000 955.720 ;
        RECT 4.400 949.600 1096.000 951.000 ;
        RECT 0.065 948.280 1096.000 949.600 ;
        RECT 0.065 946.880 1095.600 948.280 ;
        RECT 0.065 945.560 1096.000 946.880 ;
        RECT 4.400 944.160 1096.000 945.560 ;
        RECT 0.065 940.120 1096.000 944.160 ;
        RECT 4.400 938.760 1096.000 940.120 ;
        RECT 4.400 938.720 1095.600 938.760 ;
        RECT 0.065 937.360 1095.600 938.720 ;
        RECT 0.065 934.680 1096.000 937.360 ;
        RECT 4.400 933.280 1096.000 934.680 ;
        RECT 0.065 928.560 1096.000 933.280 ;
        RECT 4.400 927.160 1095.600 928.560 ;
        RECT 0.065 923.120 1096.000 927.160 ;
        RECT 4.400 921.720 1096.000 923.120 ;
        RECT 0.065 919.040 1096.000 921.720 ;
        RECT 0.065 917.680 1095.600 919.040 ;
        RECT 4.400 917.640 1095.600 917.680 ;
        RECT 4.400 916.280 1096.000 917.640 ;
        RECT 0.065 911.560 1096.000 916.280 ;
        RECT 4.400 910.160 1096.000 911.560 ;
        RECT 0.065 909.520 1096.000 910.160 ;
        RECT 0.065 908.120 1095.600 909.520 ;
        RECT 0.065 906.120 1096.000 908.120 ;
        RECT 4.400 904.720 1096.000 906.120 ;
        RECT 0.065 900.680 1096.000 904.720 ;
        RECT 4.400 899.320 1096.000 900.680 ;
        RECT 4.400 899.280 1095.600 899.320 ;
        RECT 0.065 897.920 1095.600 899.280 ;
        RECT 0.065 894.560 1096.000 897.920 ;
        RECT 4.400 893.160 1096.000 894.560 ;
        RECT 0.065 889.800 1096.000 893.160 ;
        RECT 0.065 889.120 1095.600 889.800 ;
        RECT 4.400 888.400 1095.600 889.120 ;
        RECT 4.400 887.720 1096.000 888.400 ;
        RECT 0.065 883.680 1096.000 887.720 ;
        RECT 4.400 882.280 1096.000 883.680 ;
        RECT 0.065 879.600 1096.000 882.280 ;
        RECT 0.065 878.240 1095.600 879.600 ;
        RECT 4.400 878.200 1095.600 878.240 ;
        RECT 4.400 876.840 1096.000 878.200 ;
        RECT 0.065 872.120 1096.000 876.840 ;
        RECT 4.400 870.720 1096.000 872.120 ;
        RECT 0.065 870.080 1096.000 870.720 ;
        RECT 0.065 868.680 1095.600 870.080 ;
        RECT 0.065 866.680 1096.000 868.680 ;
        RECT 4.400 865.280 1096.000 866.680 ;
        RECT 0.065 861.240 1096.000 865.280 ;
        RECT 4.400 859.880 1096.000 861.240 ;
        RECT 4.400 859.840 1095.600 859.880 ;
        RECT 0.065 858.480 1095.600 859.840 ;
        RECT 0.065 855.120 1096.000 858.480 ;
        RECT 4.400 853.720 1096.000 855.120 ;
        RECT 0.065 850.360 1096.000 853.720 ;
        RECT 0.065 849.680 1095.600 850.360 ;
        RECT 4.400 848.960 1095.600 849.680 ;
        RECT 4.400 848.280 1096.000 848.960 ;
        RECT 0.065 844.240 1096.000 848.280 ;
        RECT 4.400 842.840 1096.000 844.240 ;
        RECT 0.065 840.160 1096.000 842.840 ;
        RECT 0.065 838.800 1095.600 840.160 ;
        RECT 4.400 838.760 1095.600 838.800 ;
        RECT 4.400 837.400 1096.000 838.760 ;
        RECT 0.065 832.680 1096.000 837.400 ;
        RECT 4.400 831.280 1096.000 832.680 ;
        RECT 0.065 830.640 1096.000 831.280 ;
        RECT 0.065 829.240 1095.600 830.640 ;
        RECT 0.065 827.240 1096.000 829.240 ;
        RECT 4.400 825.840 1096.000 827.240 ;
        RECT 0.065 821.800 1096.000 825.840 ;
        RECT 4.400 821.120 1096.000 821.800 ;
        RECT 4.400 820.400 1095.600 821.120 ;
        RECT 0.065 819.720 1095.600 820.400 ;
        RECT 0.065 815.680 1096.000 819.720 ;
        RECT 4.400 814.280 1096.000 815.680 ;
        RECT 0.065 810.920 1096.000 814.280 ;
        RECT 0.065 810.240 1095.600 810.920 ;
        RECT 4.400 809.520 1095.600 810.240 ;
        RECT 4.400 808.840 1096.000 809.520 ;
        RECT 0.065 804.800 1096.000 808.840 ;
        RECT 4.400 803.400 1096.000 804.800 ;
        RECT 0.065 801.400 1096.000 803.400 ;
        RECT 0.065 800.000 1095.600 801.400 ;
        RECT 0.065 798.680 1096.000 800.000 ;
        RECT 4.400 797.280 1096.000 798.680 ;
        RECT 0.065 793.240 1096.000 797.280 ;
        RECT 4.400 791.840 1096.000 793.240 ;
        RECT 0.065 791.200 1096.000 791.840 ;
        RECT 0.065 789.800 1095.600 791.200 ;
        RECT 0.065 787.800 1096.000 789.800 ;
        RECT 4.400 786.400 1096.000 787.800 ;
        RECT 0.065 782.360 1096.000 786.400 ;
        RECT 4.400 781.680 1096.000 782.360 ;
        RECT 4.400 780.960 1095.600 781.680 ;
        RECT 0.065 780.280 1095.600 780.960 ;
        RECT 0.065 776.240 1096.000 780.280 ;
        RECT 4.400 774.840 1096.000 776.240 ;
        RECT 0.065 771.480 1096.000 774.840 ;
        RECT 0.065 770.800 1095.600 771.480 ;
        RECT 4.400 770.080 1095.600 770.800 ;
        RECT 4.400 769.400 1096.000 770.080 ;
        RECT 0.065 765.360 1096.000 769.400 ;
        RECT 4.400 763.960 1096.000 765.360 ;
        RECT 0.065 761.960 1096.000 763.960 ;
        RECT 0.065 760.560 1095.600 761.960 ;
        RECT 0.065 759.240 1096.000 760.560 ;
        RECT 4.400 757.840 1096.000 759.240 ;
        RECT 0.065 753.800 1096.000 757.840 ;
        RECT 4.400 752.400 1096.000 753.800 ;
        RECT 0.065 751.760 1096.000 752.400 ;
        RECT 0.065 750.360 1095.600 751.760 ;
        RECT 0.065 748.360 1096.000 750.360 ;
        RECT 4.400 746.960 1096.000 748.360 ;
        RECT 0.065 742.240 1096.000 746.960 ;
        RECT 4.400 740.840 1095.600 742.240 ;
        RECT 0.065 736.800 1096.000 740.840 ;
        RECT 4.400 735.400 1096.000 736.800 ;
        RECT 0.065 732.720 1096.000 735.400 ;
        RECT 0.065 731.360 1095.600 732.720 ;
        RECT 4.400 731.320 1095.600 731.360 ;
        RECT 4.400 729.960 1096.000 731.320 ;
        RECT 0.065 725.920 1096.000 729.960 ;
        RECT 4.400 724.520 1096.000 725.920 ;
        RECT 0.065 722.520 1096.000 724.520 ;
        RECT 0.065 721.120 1095.600 722.520 ;
        RECT 0.065 719.800 1096.000 721.120 ;
        RECT 4.400 718.400 1096.000 719.800 ;
        RECT 0.065 714.360 1096.000 718.400 ;
        RECT 4.400 713.000 1096.000 714.360 ;
        RECT 4.400 712.960 1095.600 713.000 ;
        RECT 0.065 711.600 1095.600 712.960 ;
        RECT 0.065 708.920 1096.000 711.600 ;
        RECT 4.400 707.520 1096.000 708.920 ;
        RECT 0.065 702.800 1096.000 707.520 ;
        RECT 4.400 701.400 1095.600 702.800 ;
        RECT 0.065 697.360 1096.000 701.400 ;
        RECT 4.400 695.960 1096.000 697.360 ;
        RECT 0.065 693.280 1096.000 695.960 ;
        RECT 0.065 691.920 1095.600 693.280 ;
        RECT 4.400 691.880 1095.600 691.920 ;
        RECT 4.400 690.520 1096.000 691.880 ;
        RECT 0.065 685.800 1096.000 690.520 ;
        RECT 4.400 684.400 1096.000 685.800 ;
        RECT 0.065 683.080 1096.000 684.400 ;
        RECT 0.065 681.680 1095.600 683.080 ;
        RECT 0.065 680.360 1096.000 681.680 ;
        RECT 4.400 678.960 1096.000 680.360 ;
        RECT 0.065 674.920 1096.000 678.960 ;
        RECT 4.400 673.560 1096.000 674.920 ;
        RECT 4.400 673.520 1095.600 673.560 ;
        RECT 0.065 672.160 1095.600 673.520 ;
        RECT 0.065 669.480 1096.000 672.160 ;
        RECT 4.400 668.080 1096.000 669.480 ;
        RECT 0.065 663.360 1096.000 668.080 ;
        RECT 4.400 661.960 1095.600 663.360 ;
        RECT 0.065 657.920 1096.000 661.960 ;
        RECT 4.400 656.520 1096.000 657.920 ;
        RECT 0.065 653.840 1096.000 656.520 ;
        RECT 0.065 652.480 1095.600 653.840 ;
        RECT 4.400 652.440 1095.600 652.480 ;
        RECT 4.400 651.080 1096.000 652.440 ;
        RECT 0.065 646.360 1096.000 651.080 ;
        RECT 4.400 644.960 1096.000 646.360 ;
        RECT 0.065 644.320 1096.000 644.960 ;
        RECT 0.065 642.920 1095.600 644.320 ;
        RECT 0.065 640.920 1096.000 642.920 ;
        RECT 4.400 639.520 1096.000 640.920 ;
        RECT 0.065 635.480 1096.000 639.520 ;
        RECT 4.400 634.120 1096.000 635.480 ;
        RECT 4.400 634.080 1095.600 634.120 ;
        RECT 0.065 632.720 1095.600 634.080 ;
        RECT 0.065 630.040 1096.000 632.720 ;
        RECT 4.400 628.640 1096.000 630.040 ;
        RECT 0.065 624.600 1096.000 628.640 ;
        RECT 0.065 623.920 1095.600 624.600 ;
        RECT 4.400 623.200 1095.600 623.920 ;
        RECT 4.400 622.520 1096.000 623.200 ;
        RECT 0.065 618.480 1096.000 622.520 ;
        RECT 4.400 617.080 1096.000 618.480 ;
        RECT 0.065 614.400 1096.000 617.080 ;
        RECT 0.065 613.040 1095.600 614.400 ;
        RECT 4.400 613.000 1095.600 613.040 ;
        RECT 4.400 611.640 1096.000 613.000 ;
        RECT 0.065 606.920 1096.000 611.640 ;
        RECT 4.400 605.520 1096.000 606.920 ;
        RECT 0.065 604.880 1096.000 605.520 ;
        RECT 0.065 603.480 1095.600 604.880 ;
        RECT 0.065 601.480 1096.000 603.480 ;
        RECT 4.400 600.080 1096.000 601.480 ;
        RECT 0.065 596.040 1096.000 600.080 ;
        RECT 4.400 594.680 1096.000 596.040 ;
        RECT 4.400 594.640 1095.600 594.680 ;
        RECT 0.065 593.280 1095.600 594.640 ;
        RECT 0.065 589.920 1096.000 593.280 ;
        RECT 4.400 588.520 1096.000 589.920 ;
        RECT 0.065 585.160 1096.000 588.520 ;
        RECT 0.065 584.480 1095.600 585.160 ;
        RECT 4.400 583.760 1095.600 584.480 ;
        RECT 4.400 583.080 1096.000 583.760 ;
        RECT 0.065 579.040 1096.000 583.080 ;
        RECT 4.400 577.640 1096.000 579.040 ;
        RECT 0.065 574.960 1096.000 577.640 ;
        RECT 0.065 573.600 1095.600 574.960 ;
        RECT 4.400 573.560 1095.600 573.600 ;
        RECT 4.400 572.200 1096.000 573.560 ;
        RECT 0.065 567.480 1096.000 572.200 ;
        RECT 4.400 566.080 1096.000 567.480 ;
        RECT 0.065 565.440 1096.000 566.080 ;
        RECT 0.065 564.040 1095.600 565.440 ;
        RECT 0.065 562.040 1096.000 564.040 ;
        RECT 4.400 560.640 1096.000 562.040 ;
        RECT 0.065 556.600 1096.000 560.640 ;
        RECT 4.400 555.920 1096.000 556.600 ;
        RECT 4.400 555.200 1095.600 555.920 ;
        RECT 0.065 554.520 1095.600 555.200 ;
        RECT 0.065 550.480 1096.000 554.520 ;
        RECT 4.400 549.080 1096.000 550.480 ;
        RECT 0.065 545.720 1096.000 549.080 ;
        RECT 0.065 545.040 1095.600 545.720 ;
        RECT 4.400 544.320 1095.600 545.040 ;
        RECT 4.400 543.640 1096.000 544.320 ;
        RECT 0.065 539.600 1096.000 543.640 ;
        RECT 4.400 538.200 1096.000 539.600 ;
        RECT 0.065 536.200 1096.000 538.200 ;
        RECT 0.065 534.800 1095.600 536.200 ;
        RECT 0.065 533.480 1096.000 534.800 ;
        RECT 4.400 532.080 1096.000 533.480 ;
        RECT 0.065 528.040 1096.000 532.080 ;
        RECT 4.400 526.640 1096.000 528.040 ;
        RECT 0.065 526.000 1096.000 526.640 ;
        RECT 0.065 524.600 1095.600 526.000 ;
        RECT 0.065 522.600 1096.000 524.600 ;
        RECT 4.400 521.200 1096.000 522.600 ;
        RECT 0.065 517.160 1096.000 521.200 ;
        RECT 4.400 516.480 1096.000 517.160 ;
        RECT 4.400 515.760 1095.600 516.480 ;
        RECT 0.065 515.080 1095.600 515.760 ;
        RECT 0.065 511.040 1096.000 515.080 ;
        RECT 4.400 509.640 1096.000 511.040 ;
        RECT 0.065 506.280 1096.000 509.640 ;
        RECT 0.065 505.600 1095.600 506.280 ;
        RECT 4.400 504.880 1095.600 505.600 ;
        RECT 4.400 504.200 1096.000 504.880 ;
        RECT 0.065 500.160 1096.000 504.200 ;
        RECT 4.400 498.760 1096.000 500.160 ;
        RECT 0.065 496.760 1096.000 498.760 ;
        RECT 0.065 495.360 1095.600 496.760 ;
        RECT 0.065 494.040 1096.000 495.360 ;
        RECT 4.400 492.640 1096.000 494.040 ;
        RECT 0.065 488.600 1096.000 492.640 ;
        RECT 4.400 487.200 1096.000 488.600 ;
        RECT 0.065 486.560 1096.000 487.200 ;
        RECT 0.065 485.160 1095.600 486.560 ;
        RECT 0.065 483.160 1096.000 485.160 ;
        RECT 4.400 481.760 1096.000 483.160 ;
        RECT 0.065 477.040 1096.000 481.760 ;
        RECT 4.400 475.640 1095.600 477.040 ;
        RECT 0.065 471.600 1096.000 475.640 ;
        RECT 4.400 470.200 1096.000 471.600 ;
        RECT 0.065 466.840 1096.000 470.200 ;
        RECT 0.065 466.160 1095.600 466.840 ;
        RECT 4.400 465.440 1095.600 466.160 ;
        RECT 4.400 464.760 1096.000 465.440 ;
        RECT 0.065 460.720 1096.000 464.760 ;
        RECT 4.400 459.320 1096.000 460.720 ;
        RECT 0.065 457.320 1096.000 459.320 ;
        RECT 0.065 455.920 1095.600 457.320 ;
        RECT 0.065 454.600 1096.000 455.920 ;
        RECT 4.400 453.200 1096.000 454.600 ;
        RECT 0.065 449.160 1096.000 453.200 ;
        RECT 4.400 447.800 1096.000 449.160 ;
        RECT 4.400 447.760 1095.600 447.800 ;
        RECT 0.065 446.400 1095.600 447.760 ;
        RECT 0.065 443.720 1096.000 446.400 ;
        RECT 4.400 442.320 1096.000 443.720 ;
        RECT 0.065 437.600 1096.000 442.320 ;
        RECT 4.400 436.200 1095.600 437.600 ;
        RECT 0.065 432.160 1096.000 436.200 ;
        RECT 4.400 430.760 1096.000 432.160 ;
        RECT 0.065 428.080 1096.000 430.760 ;
        RECT 0.065 426.720 1095.600 428.080 ;
        RECT 4.400 426.680 1095.600 426.720 ;
        RECT 4.400 425.320 1096.000 426.680 ;
        RECT 0.065 421.280 1096.000 425.320 ;
        RECT 4.400 419.880 1096.000 421.280 ;
        RECT 0.065 417.880 1096.000 419.880 ;
        RECT 0.065 416.480 1095.600 417.880 ;
        RECT 0.065 415.160 1096.000 416.480 ;
        RECT 4.400 413.760 1096.000 415.160 ;
        RECT 0.065 409.720 1096.000 413.760 ;
        RECT 4.400 408.360 1096.000 409.720 ;
        RECT 4.400 408.320 1095.600 408.360 ;
        RECT 0.065 406.960 1095.600 408.320 ;
        RECT 0.065 404.280 1096.000 406.960 ;
        RECT 4.400 402.880 1096.000 404.280 ;
        RECT 0.065 398.160 1096.000 402.880 ;
        RECT 4.400 396.760 1095.600 398.160 ;
        RECT 0.065 392.720 1096.000 396.760 ;
        RECT 4.400 391.320 1096.000 392.720 ;
        RECT 0.065 388.640 1096.000 391.320 ;
        RECT 0.065 387.280 1095.600 388.640 ;
        RECT 4.400 387.240 1095.600 387.280 ;
        RECT 4.400 385.880 1096.000 387.240 ;
        RECT 0.065 381.160 1096.000 385.880 ;
        RECT 4.400 379.760 1096.000 381.160 ;
        RECT 0.065 378.440 1096.000 379.760 ;
        RECT 0.065 377.040 1095.600 378.440 ;
        RECT 0.065 375.720 1096.000 377.040 ;
        RECT 4.400 374.320 1096.000 375.720 ;
        RECT 0.065 370.280 1096.000 374.320 ;
        RECT 4.400 368.920 1096.000 370.280 ;
        RECT 4.400 368.880 1095.600 368.920 ;
        RECT 0.065 367.520 1095.600 368.880 ;
        RECT 0.065 364.840 1096.000 367.520 ;
        RECT 4.400 363.440 1096.000 364.840 ;
        RECT 0.065 359.400 1096.000 363.440 ;
        RECT 0.065 358.720 1095.600 359.400 ;
        RECT 4.400 358.000 1095.600 358.720 ;
        RECT 4.400 357.320 1096.000 358.000 ;
        RECT 0.065 353.280 1096.000 357.320 ;
        RECT 4.400 351.880 1096.000 353.280 ;
        RECT 0.065 349.200 1096.000 351.880 ;
        RECT 0.065 347.840 1095.600 349.200 ;
        RECT 4.400 347.800 1095.600 347.840 ;
        RECT 4.400 346.440 1096.000 347.800 ;
        RECT 0.065 341.720 1096.000 346.440 ;
        RECT 4.400 340.320 1096.000 341.720 ;
        RECT 0.065 339.680 1096.000 340.320 ;
        RECT 0.065 338.280 1095.600 339.680 ;
        RECT 0.065 336.280 1096.000 338.280 ;
        RECT 4.400 334.880 1096.000 336.280 ;
        RECT 0.065 330.840 1096.000 334.880 ;
        RECT 4.400 329.480 1096.000 330.840 ;
        RECT 4.400 329.440 1095.600 329.480 ;
        RECT 0.065 328.080 1095.600 329.440 ;
        RECT 0.065 324.720 1096.000 328.080 ;
        RECT 4.400 323.320 1096.000 324.720 ;
        RECT 0.065 319.960 1096.000 323.320 ;
        RECT 0.065 319.280 1095.600 319.960 ;
        RECT 4.400 318.560 1095.600 319.280 ;
        RECT 4.400 317.880 1096.000 318.560 ;
        RECT 0.065 313.840 1096.000 317.880 ;
        RECT 4.400 312.440 1096.000 313.840 ;
        RECT 0.065 309.760 1096.000 312.440 ;
        RECT 0.065 308.400 1095.600 309.760 ;
        RECT 4.400 308.360 1095.600 308.400 ;
        RECT 4.400 307.000 1096.000 308.360 ;
        RECT 0.065 302.280 1096.000 307.000 ;
        RECT 4.400 300.880 1096.000 302.280 ;
        RECT 0.065 300.240 1096.000 300.880 ;
        RECT 0.065 298.840 1095.600 300.240 ;
        RECT 0.065 296.840 1096.000 298.840 ;
        RECT 4.400 295.440 1096.000 296.840 ;
        RECT 0.065 291.400 1096.000 295.440 ;
        RECT 4.400 290.040 1096.000 291.400 ;
        RECT 4.400 290.000 1095.600 290.040 ;
        RECT 0.065 288.640 1095.600 290.000 ;
        RECT 0.065 285.280 1096.000 288.640 ;
        RECT 4.400 283.880 1096.000 285.280 ;
        RECT 0.065 280.520 1096.000 283.880 ;
        RECT 0.065 279.840 1095.600 280.520 ;
        RECT 4.400 279.120 1095.600 279.840 ;
        RECT 4.400 278.440 1096.000 279.120 ;
        RECT 0.065 274.400 1096.000 278.440 ;
        RECT 4.400 273.000 1096.000 274.400 ;
        RECT 0.065 271.000 1096.000 273.000 ;
        RECT 0.065 269.600 1095.600 271.000 ;
        RECT 0.065 268.280 1096.000 269.600 ;
        RECT 4.400 266.880 1096.000 268.280 ;
        RECT 0.065 262.840 1096.000 266.880 ;
        RECT 4.400 261.440 1096.000 262.840 ;
        RECT 0.065 260.800 1096.000 261.440 ;
        RECT 0.065 259.400 1095.600 260.800 ;
        RECT 0.065 257.400 1096.000 259.400 ;
        RECT 4.400 256.000 1096.000 257.400 ;
        RECT 0.065 251.960 1096.000 256.000 ;
        RECT 4.400 251.280 1096.000 251.960 ;
        RECT 4.400 250.560 1095.600 251.280 ;
        RECT 0.065 249.880 1095.600 250.560 ;
        RECT 0.065 245.840 1096.000 249.880 ;
        RECT 4.400 244.440 1096.000 245.840 ;
        RECT 0.065 241.080 1096.000 244.440 ;
        RECT 0.065 240.400 1095.600 241.080 ;
        RECT 4.400 239.680 1095.600 240.400 ;
        RECT 4.400 239.000 1096.000 239.680 ;
        RECT 0.065 234.960 1096.000 239.000 ;
        RECT 4.400 233.560 1096.000 234.960 ;
        RECT 0.065 231.560 1096.000 233.560 ;
        RECT 0.065 230.160 1095.600 231.560 ;
        RECT 0.065 228.840 1096.000 230.160 ;
        RECT 4.400 227.440 1096.000 228.840 ;
        RECT 0.065 223.400 1096.000 227.440 ;
        RECT 4.400 222.000 1096.000 223.400 ;
        RECT 0.065 221.360 1096.000 222.000 ;
        RECT 0.065 219.960 1095.600 221.360 ;
        RECT 0.065 217.960 1096.000 219.960 ;
        RECT 4.400 216.560 1096.000 217.960 ;
        RECT 0.065 212.520 1096.000 216.560 ;
        RECT 4.400 211.840 1096.000 212.520 ;
        RECT 4.400 211.120 1095.600 211.840 ;
        RECT 0.065 210.440 1095.600 211.120 ;
        RECT 0.065 206.400 1096.000 210.440 ;
        RECT 4.400 205.000 1096.000 206.400 ;
        RECT 0.065 201.640 1096.000 205.000 ;
        RECT 0.065 200.960 1095.600 201.640 ;
        RECT 4.400 200.240 1095.600 200.960 ;
        RECT 4.400 199.560 1096.000 200.240 ;
        RECT 0.065 195.520 1096.000 199.560 ;
        RECT 4.400 194.120 1096.000 195.520 ;
        RECT 0.065 192.120 1096.000 194.120 ;
        RECT 0.065 190.720 1095.600 192.120 ;
        RECT 0.065 189.400 1096.000 190.720 ;
        RECT 4.400 188.000 1096.000 189.400 ;
        RECT 0.065 183.960 1096.000 188.000 ;
        RECT 4.400 182.600 1096.000 183.960 ;
        RECT 4.400 182.560 1095.600 182.600 ;
        RECT 0.065 181.200 1095.600 182.560 ;
        RECT 0.065 178.520 1096.000 181.200 ;
        RECT 4.400 177.120 1096.000 178.520 ;
        RECT 0.065 172.400 1096.000 177.120 ;
        RECT 4.400 171.000 1095.600 172.400 ;
        RECT 0.065 166.960 1096.000 171.000 ;
        RECT 4.400 165.560 1096.000 166.960 ;
        RECT 0.065 162.880 1096.000 165.560 ;
        RECT 0.065 161.520 1095.600 162.880 ;
        RECT 4.400 161.480 1095.600 161.520 ;
        RECT 4.400 160.120 1096.000 161.480 ;
        RECT 0.065 156.080 1096.000 160.120 ;
        RECT 4.400 154.680 1096.000 156.080 ;
        RECT 0.065 152.680 1096.000 154.680 ;
        RECT 0.065 151.280 1095.600 152.680 ;
        RECT 0.065 149.960 1096.000 151.280 ;
        RECT 4.400 148.560 1096.000 149.960 ;
        RECT 0.065 144.520 1096.000 148.560 ;
        RECT 4.400 143.160 1096.000 144.520 ;
        RECT 4.400 143.120 1095.600 143.160 ;
        RECT 0.065 141.760 1095.600 143.120 ;
        RECT 0.065 139.080 1096.000 141.760 ;
        RECT 4.400 137.680 1096.000 139.080 ;
        RECT 0.065 132.960 1096.000 137.680 ;
        RECT 4.400 131.560 1095.600 132.960 ;
        RECT 0.065 127.520 1096.000 131.560 ;
        RECT 4.400 126.120 1096.000 127.520 ;
        RECT 0.065 123.440 1096.000 126.120 ;
        RECT 0.065 122.080 1095.600 123.440 ;
        RECT 4.400 122.040 1095.600 122.080 ;
        RECT 4.400 120.680 1096.000 122.040 ;
        RECT 0.065 115.960 1096.000 120.680 ;
        RECT 4.400 114.560 1096.000 115.960 ;
        RECT 0.065 113.240 1096.000 114.560 ;
        RECT 0.065 111.840 1095.600 113.240 ;
        RECT 0.065 110.520 1096.000 111.840 ;
        RECT 4.400 109.120 1096.000 110.520 ;
        RECT 0.065 105.080 1096.000 109.120 ;
        RECT 4.400 103.720 1096.000 105.080 ;
        RECT 4.400 103.680 1095.600 103.720 ;
        RECT 0.065 102.320 1095.600 103.680 ;
        RECT 0.065 99.640 1096.000 102.320 ;
        RECT 4.400 98.240 1096.000 99.640 ;
        RECT 0.065 94.200 1096.000 98.240 ;
        RECT 0.065 93.520 1095.600 94.200 ;
        RECT 4.400 92.800 1095.600 93.520 ;
        RECT 4.400 92.120 1096.000 92.800 ;
        RECT 0.065 88.080 1096.000 92.120 ;
        RECT 4.400 86.680 1096.000 88.080 ;
        RECT 0.065 84.000 1096.000 86.680 ;
        RECT 0.065 82.640 1095.600 84.000 ;
        RECT 4.400 82.600 1095.600 82.640 ;
        RECT 4.400 81.240 1096.000 82.600 ;
        RECT 0.065 76.520 1096.000 81.240 ;
        RECT 4.400 75.120 1096.000 76.520 ;
        RECT 0.065 74.480 1096.000 75.120 ;
        RECT 0.065 73.080 1095.600 74.480 ;
        RECT 0.065 71.080 1096.000 73.080 ;
        RECT 4.400 69.680 1096.000 71.080 ;
        RECT 0.065 65.640 1096.000 69.680 ;
        RECT 4.400 64.280 1096.000 65.640 ;
        RECT 4.400 64.240 1095.600 64.280 ;
        RECT 0.065 62.880 1095.600 64.240 ;
        RECT 0.065 59.520 1096.000 62.880 ;
        RECT 4.400 58.120 1096.000 59.520 ;
        RECT 0.065 54.760 1096.000 58.120 ;
        RECT 0.065 54.080 1095.600 54.760 ;
        RECT 4.400 53.360 1095.600 54.080 ;
        RECT 4.400 52.680 1096.000 53.360 ;
        RECT 0.065 48.640 1096.000 52.680 ;
        RECT 4.400 47.240 1096.000 48.640 ;
        RECT 0.065 44.560 1096.000 47.240 ;
        RECT 0.065 43.200 1095.600 44.560 ;
        RECT 4.400 43.160 1095.600 43.200 ;
        RECT 4.400 41.800 1096.000 43.160 ;
        RECT 0.065 37.080 1096.000 41.800 ;
        RECT 4.400 35.680 1096.000 37.080 ;
        RECT 0.065 35.040 1096.000 35.680 ;
        RECT 0.065 33.640 1095.600 35.040 ;
        RECT 0.065 31.640 1096.000 33.640 ;
        RECT 4.400 30.240 1096.000 31.640 ;
        RECT 0.065 26.200 1096.000 30.240 ;
        RECT 4.400 24.840 1096.000 26.200 ;
        RECT 4.400 24.800 1095.600 24.840 ;
        RECT 0.065 23.440 1095.600 24.800 ;
        RECT 0.065 20.080 1096.000 23.440 ;
        RECT 4.400 18.680 1096.000 20.080 ;
        RECT 0.065 15.320 1096.000 18.680 ;
        RECT 0.065 14.640 1095.600 15.320 ;
        RECT 4.400 13.920 1095.600 14.640 ;
        RECT 4.400 13.240 1096.000 13.920 ;
        RECT 0.065 9.200 1096.000 13.240 ;
        RECT 4.400 7.800 1096.000 9.200 ;
        RECT 0.065 5.800 1096.000 7.800 ;
        RECT 0.065 4.400 1095.600 5.800 ;
        RECT 0.065 3.760 1096.000 4.400 ;
        RECT 4.400 2.895 1096.000 3.760 ;
      LAYER met4 ;
        RECT 1.215 11.735 20.640 1087.145 ;
        RECT 23.040 11.735 97.440 1087.145 ;
        RECT 99.840 11.735 174.240 1087.145 ;
        RECT 176.640 11.735 226.945 1087.145 ;
  END
END WB_InterConnect
END LIBRARY

